VERSION 5.8 ;
BUSBITCHARS "[]" ;
DIVIDERCHAR "/" ;
UNITS
    DATABASE MICRONS 1000 ;
END UNITS

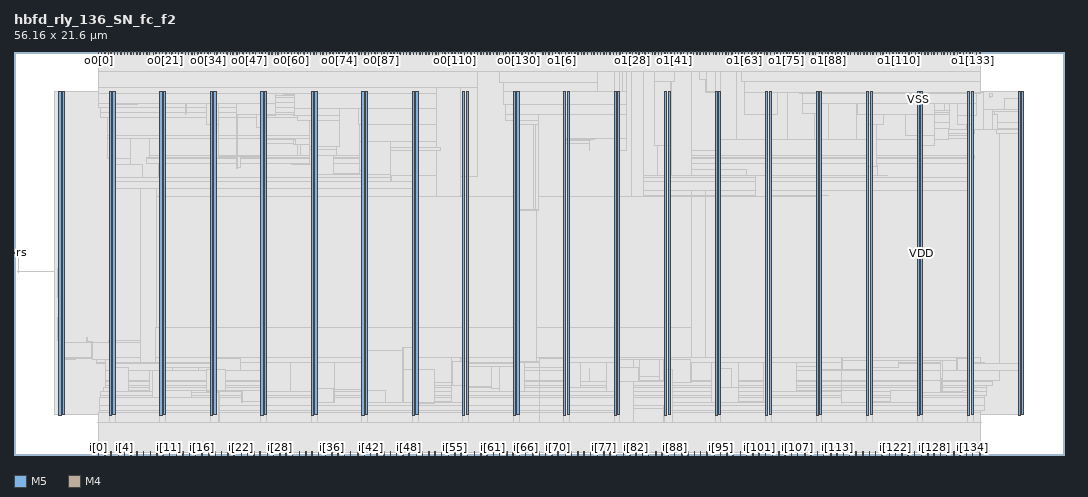
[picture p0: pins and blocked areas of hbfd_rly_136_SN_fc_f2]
MACRO hbfd_rly_136_SN_fc_f2
  FOREIGN hbfd_rly_136_SN_fc_f2 0 0 ;
  CLASS BLOCK ;
  SIZE 56.16 BY 21.6 ;
  PIN clk_in
    DIRECTION INPUT ;
    USE SIGNAL ;
    PORT
      LAYER M5 ;
        RECT  28.08 0 28.104 0.192 ;
    END
  END clk_in
  PIN clk_out0
    DIRECTION OUTPUT ;
    USE SIGNAL ;
    PORT
      LAYER M5 ;
        RECT  16.176 21.408 16.2 21.6 ;
    END
  END clk_out0
  PIN clk_out1
    DIRECTION OUTPUT ;
    USE SIGNAL ;
    PORT
      LAYER M5 ;
        RECT  39.936 21.408 39.96 21.6 ;
    END
  END clk_out1
  PIN i[0]
    DIRECTION INPUT ;
    USE SIGNAL ;
    PORT
      LAYER M5 ;
        RECT  4.512 0 4.536 0.192 ;
    END
  END i[0]
  PIN i[100]
    DIRECTION INPUT ;
    USE SIGNAL ;
    PORT
      LAYER M5 ;
        RECT  39.504 0 39.528 0.192 ;
    END
  END i[100]
  PIN i[101]
    DIRECTION INPUT ;
    USE SIGNAL ;
    PORT
      LAYER M5 ;
        RECT  39.84 0 39.864 0.192 ;
    END
  END i[101]
  PIN i[102]
    DIRECTION INPUT ;
    USE SIGNAL ;
    PORT
      LAYER M5 ;
        RECT  40.176 0 40.2 0.192 ;
    END
  END i[102]
  PIN i[103]
    DIRECTION INPUT ;
    USE SIGNAL ;
    PORT
      LAYER M5 ;
        RECT  40.56 0 40.584 0.192 ;
    END
  END i[103]
  PIN i[104]
    DIRECTION INPUT ;
    USE SIGNAL ;
    PORT
      LAYER M5 ;
        RECT  40.896 0 40.92 0.192 ;
    END
  END i[104]
  PIN i[105]
    DIRECTION INPUT ;
    USE SIGNAL ;
    PORT
      LAYER M5 ;
        RECT  41.232 0 41.256 0.192 ;
    END
  END i[105]
  PIN i[106]
    DIRECTION INPUT ;
    USE SIGNAL ;
    PORT
      LAYER M5 ;
        RECT  41.568 0 41.592 0.192 ;
    END
  END i[106]
  PIN i[107]
    DIRECTION INPUT ;
    USE SIGNAL ;
    PORT
      LAYER M5 ;
        RECT  41.904 0 41.928 0.192 ;
    END
  END i[107]
  PIN i[108]
    DIRECTION INPUT ;
    USE SIGNAL ;
    PORT
      LAYER M5 ;
        RECT  42.288 0 42.312 0.192 ;
    END
  END i[108]
  PIN i[109]
    DIRECTION INPUT ;
    USE SIGNAL ;
    PORT
      LAYER M5 ;
        RECT  42.624 0 42.648 0.192 ;
    END
  END i[109]
  PIN i[10]
    DIRECTION INPUT ;
    USE SIGNAL ;
    PORT
      LAYER M5 ;
        RECT  7.968 0 7.992 0.192 ;
    END
  END i[10]
  PIN i[110]
    DIRECTION INPUT ;
    USE SIGNAL ;
    PORT
      LAYER M5 ;
        RECT  42.96 0 42.984 0.192 ;
    END
  END i[110]
  PIN i[111]
    DIRECTION INPUT ;
    USE SIGNAL ;
    PORT
      LAYER M5 ;
        RECT  43.296 0 43.32 0.192 ;
    END
  END i[111]
  PIN i[112]
    DIRECTION INPUT ;
    USE SIGNAL ;
    PORT
      LAYER M5 ;
        RECT  43.68 0 43.704 0.192 ;
    END
  END i[112]
  PIN i[113]
    DIRECTION INPUT ;
    USE SIGNAL ;
    PORT
      LAYER M5 ;
        RECT  44.016 0 44.04 0.192 ;
    END
  END i[113]
  PIN i[114]
    DIRECTION INPUT ;
    USE SIGNAL ;
    PORT
      LAYER M5 ;
        RECT  44.352 0 44.376 0.192 ;
    END
  END i[114]
  PIN i[115]
    DIRECTION INPUT ;
    USE SIGNAL ;
    PORT
      LAYER M5 ;
        RECT  44.688 0 44.712 0.192 ;
    END
  END i[115]
  PIN i[116]
    DIRECTION INPUT ;
    USE SIGNAL ;
    PORT
      LAYER M5 ;
        RECT  45.024 0 45.048 0.192 ;
    END
  END i[116]
  PIN i[117]
    DIRECTION INPUT ;
    USE SIGNAL ;
    PORT
      LAYER M5 ;
        RECT  45.408 0 45.432 0.192 ;
    END
  END i[117]
  PIN i[118]
    DIRECTION INPUT ;
    USE SIGNAL ;
    PORT
      LAYER M5 ;
        RECT  45.744 0 45.768 0.192 ;
    END
  END i[118]
  PIN i[119]
    DIRECTION INPUT ;
    USE SIGNAL ;
    PORT
      LAYER M5 ;
        RECT  46.08 0 46.104 0.192 ;
    END
  END i[119]
  PIN i[11]
    DIRECTION INPUT ;
    USE SIGNAL ;
    PORT
      LAYER M5 ;
        RECT  8.304 0 8.328 0.192 ;
    END
  END i[11]
  PIN i[120]
    DIRECTION INPUT ;
    USE SIGNAL ;
    PORT
      LAYER M5 ;
        RECT  46.416 0 46.44 0.192 ;
    END
  END i[120]
  PIN i[121]
    DIRECTION INPUT ;
    USE SIGNAL ;
    PORT
      LAYER M5 ;
        RECT  46.8 0 46.824 0.192 ;
    END
  END i[121]
  PIN i[122]
    DIRECTION INPUT ;
    USE SIGNAL ;
    PORT
      LAYER M5 ;
        RECT  47.136 0 47.16 0.192 ;
    END
  END i[122]
  PIN i[123]
    DIRECTION INPUT ;
    USE SIGNAL ;
    PORT
      LAYER M5 ;
        RECT  47.472 0 47.496 0.192 ;
    END
  END i[123]
  PIN i[124]
    DIRECTION INPUT ;
    USE SIGNAL ;
    PORT
      LAYER M5 ;
        RECT  47.808 0 47.832 0.192 ;
    END
  END i[124]
  PIN i[125]
    DIRECTION INPUT ;
    USE SIGNAL ;
    PORT
      LAYER M5 ;
        RECT  48.144 0 48.168 0.192 ;
    END
  END i[125]
  PIN i[126]
    DIRECTION INPUT ;
    USE SIGNAL ;
    PORT
      LAYER M5 ;
        RECT  48.528 0 48.552 0.192 ;
    END
  END i[126]
  PIN i[127]
    DIRECTION INPUT ;
    USE SIGNAL ;
    PORT
      LAYER M5 ;
        RECT  48.864 0 48.888 0.192 ;
    END
  END i[127]
  PIN i[128]
    DIRECTION INPUT ;
    USE SIGNAL ;
    PORT
      LAYER M5 ;
        RECT  49.2 0 49.224 0.192 ;
    END
  END i[128]
  PIN i[129]
    DIRECTION INPUT ;
    USE SIGNAL ;
    PORT
      LAYER M5 ;
        RECT  49.536 0 49.56 0.192 ;
    END
  END i[129]
  PIN i[12]
    DIRECTION INPUT ;
    USE SIGNAL ;
    PORT
      LAYER M5 ;
        RECT  8.688 0 8.712 0.192 ;
    END
  END i[12]
  PIN i[130]
    DIRECTION INPUT ;
    USE SIGNAL ;
    PORT
      LAYER M5 ;
        RECT  49.872 0 49.896 0.192 ;
    END
  END i[130]
  PIN i[131]
    DIRECTION INPUT ;
    USE SIGNAL ;
    PORT
      LAYER M5 ;
        RECT  50.256 0 50.28 0.192 ;
    END
  END i[131]
  PIN i[132]
    DIRECTION INPUT ;
    USE SIGNAL ;
    PORT
      LAYER M5 ;
        RECT  50.592 0 50.616 0.192 ;
    END
  END i[132]
  PIN i[133]
    DIRECTION INPUT ;
    USE SIGNAL ;
    PORT
      LAYER M5 ;
        RECT  50.928 0 50.952 0.192 ;
    END
  END i[133]
  PIN i[134]
    DIRECTION INPUT ;
    USE SIGNAL ;
    PORT
      LAYER M5 ;
        RECT  51.264 0 51.288 0.192 ;
    END
  END i[134]
  PIN i[135]
    DIRECTION INPUT ;
    USE SIGNAL ;
    PORT
      LAYER M5 ;
        RECT  51.648 0 51.672 0.192 ;
    END
  END i[135]
  PIN i[13]
    DIRECTION INPUT ;
    USE SIGNAL ;
    PORT
      LAYER M5 ;
        RECT  9.024 0 9.048 0.192 ;
    END
  END i[13]
  PIN i[14]
    DIRECTION INPUT ;
    USE SIGNAL ;
    PORT
      LAYER M5 ;
        RECT  9.36 0 9.384 0.192 ;
    END
  END i[14]
  PIN i[15]
    DIRECTION INPUT ;
    USE SIGNAL ;
    PORT
      LAYER M5 ;
        RECT  9.696 0 9.72 0.192 ;
    END
  END i[15]
  PIN i[16]
    DIRECTION INPUT ;
    USE SIGNAL ;
    PORT
      LAYER M5 ;
        RECT  10.032 0 10.056 0.192 ;
    END
  END i[16]
  PIN i[17]
    DIRECTION INPUT ;
    USE SIGNAL ;
    PORT
      LAYER M5 ;
        RECT  10.416 0 10.44 0.192 ;
    END
  END i[17]
  PIN i[18]
    DIRECTION INPUT ;
    USE SIGNAL ;
    PORT
      LAYER M5 ;
        RECT  10.752 0 10.776 0.192 ;
    END
  END i[18]
  PIN i[19]
    DIRECTION INPUT ;
    USE SIGNAL ;
    PORT
      LAYER M5 ;
        RECT  11.088 0 11.112 0.192 ;
    END
  END i[19]
  PIN i[1]
    DIRECTION INPUT ;
    USE SIGNAL ;
    PORT
      LAYER M5 ;
        RECT  4.848 0 4.872 0.192 ;
    END
  END i[1]
  PIN i[20]
    DIRECTION INPUT ;
    USE SIGNAL ;
    PORT
      LAYER M5 ;
        RECT  11.424 0 11.448 0.192 ;
    END
  END i[20]
  PIN i[21]
    DIRECTION INPUT ;
    USE SIGNAL ;
    PORT
      LAYER M5 ;
        RECT  11.76 0 11.784 0.192 ;
    END
  END i[21]
  PIN i[22]
    DIRECTION INPUT ;
    USE SIGNAL ;
    PORT
      LAYER M5 ;
        RECT  12.144 0 12.168 0.192 ;
    END
  END i[22]
  PIN i[23]
    DIRECTION INPUT ;
    USE SIGNAL ;
    PORT
      LAYER M5 ;
        RECT  12.48 0 12.504 0.192 ;
    END
  END i[23]
  PIN i[24]
    DIRECTION INPUT ;
    USE SIGNAL ;
    PORT
      LAYER M5 ;
        RECT  12.816 0 12.84 0.192 ;
    END
  END i[24]
  PIN i[25]
    DIRECTION INPUT ;
    USE SIGNAL ;
    PORT
      LAYER M5 ;
        RECT  13.152 0 13.176 0.192 ;
    END
  END i[25]
  PIN i[26]
    DIRECTION INPUT ;
    USE SIGNAL ;
    PORT
      LAYER M5 ;
        RECT  13.536 0 13.56 0.192 ;
    END
  END i[26]
  PIN i[27]
    DIRECTION INPUT ;
    USE SIGNAL ;
    PORT
      LAYER M5 ;
        RECT  13.872 0 13.896 0.192 ;
    END
  END i[27]
  PIN i[28]
    DIRECTION INPUT ;
    USE SIGNAL ;
    PORT
      LAYER M5 ;
        RECT  14.208 0 14.232 0.192 ;
    END
  END i[28]
  PIN i[29]
    DIRECTION INPUT ;
    USE SIGNAL ;
    PORT
      LAYER M5 ;
        RECT  14.544 0 14.568 0.192 ;
    END
  END i[29]
  PIN i[2]
    DIRECTION INPUT ;
    USE SIGNAL ;
    PORT
      LAYER M5 ;
        RECT  5.184 0 5.208 0.192 ;
    END
  END i[2]
  PIN i[30]
    DIRECTION INPUT ;
    USE SIGNAL ;
    PORT
      LAYER M5 ;
        RECT  14.88 0 14.904 0.192 ;
    END
  END i[30]
  PIN i[31]
    DIRECTION INPUT ;
    USE SIGNAL ;
    PORT
      LAYER M5 ;
        RECT  15.264 0 15.288 0.192 ;
    END
  END i[31]
  PIN i[32]
    DIRECTION INPUT ;
    USE SIGNAL ;
    PORT
      LAYER M5 ;
        RECT  15.6 0 15.624 0.192 ;
    END
  END i[32]
  PIN i[33]
    DIRECTION INPUT ;
    USE SIGNAL ;
    PORT
      LAYER M5 ;
        RECT  15.936 0 15.96 0.192 ;
    END
  END i[33]
  PIN i[34]
    DIRECTION INPUT ;
    USE SIGNAL ;
    PORT
      LAYER M5 ;
        RECT  16.272 0 16.296 0.192 ;
    END
  END i[34]
  PIN i[35]
    DIRECTION INPUT ;
    USE SIGNAL ;
    PORT
      LAYER M5 ;
        RECT  16.656 0 16.68 0.192 ;
    END
  END i[35]
  PIN i[36]
    DIRECTION INPUT ;
    USE SIGNAL ;
    PORT
      LAYER M5 ;
        RECT  16.992 0 17.016 0.192 ;
    END
  END i[36]
  PIN i[37]
    DIRECTION INPUT ;
    USE SIGNAL ;
    PORT
      LAYER M5 ;
        RECT  17.328 0 17.352 0.192 ;
    END
  END i[37]
  PIN i[38]
    DIRECTION INPUT ;
    USE SIGNAL ;
    PORT
      LAYER M5 ;
        RECT  17.664 0 17.688 0.192 ;
    END
  END i[38]
  PIN i[39]
    DIRECTION INPUT ;
    USE SIGNAL ;
    PORT
      LAYER M5 ;
        RECT  18 0 18.024 0.192 ;
    END
  END i[39]
  PIN i[3]
    DIRECTION INPUT ;
    USE SIGNAL ;
    PORT
      LAYER M5 ;
        RECT  5.568 0 5.592 0.192 ;
    END
  END i[3]
  PIN i[40]
    DIRECTION INPUT ;
    USE SIGNAL ;
    PORT
      LAYER M5 ;
        RECT  18.384 0 18.408 0.192 ;
    END
  END i[40]
  PIN i[41]
    DIRECTION INPUT ;
    USE SIGNAL ;
    PORT
      LAYER M5 ;
        RECT  18.72 0 18.744 0.192 ;
    END
  END i[41]
  PIN i[42]
    DIRECTION INPUT ;
    USE SIGNAL ;
    PORT
      LAYER M5 ;
        RECT  19.056 0 19.08 0.192 ;
    END
  END i[42]
  PIN i[43]
    DIRECTION INPUT ;
    USE SIGNAL ;
    PORT
      LAYER M5 ;
        RECT  19.392 0 19.416 0.192 ;
    END
  END i[43]
  PIN i[44]
    DIRECTION INPUT ;
    USE SIGNAL ;
    PORT
      LAYER M5 ;
        RECT  19.776 0 19.8 0.192 ;
    END
  END i[44]
  PIN i[45]
    DIRECTION INPUT ;
    USE SIGNAL ;
    PORT
      LAYER M5 ;
        RECT  20.112 0 20.136 0.192 ;
    END
  END i[45]
  PIN i[46]
    DIRECTION INPUT ;
    USE SIGNAL ;
    PORT
      LAYER M5 ;
        RECT  20.448 0 20.472 0.192 ;
    END
  END i[46]
  PIN i[47]
    DIRECTION INPUT ;
    USE SIGNAL ;
    PORT
      LAYER M5 ;
        RECT  20.784 0 20.808 0.192 ;
    END
  END i[47]
  PIN i[48]
    DIRECTION INPUT ;
    USE SIGNAL ;
    PORT
      LAYER M5 ;
        RECT  21.12 0 21.144 0.192 ;
    END
  END i[48]
  PIN i[49]
    DIRECTION INPUT ;
    USE SIGNAL ;
    PORT
      LAYER M5 ;
        RECT  21.504 0 21.528 0.192 ;
    END
  END i[49]
  PIN i[4]
    DIRECTION INPUT ;
    USE SIGNAL ;
    PORT
      LAYER M5 ;
        RECT  5.904 0 5.928 0.192 ;
    END
  END i[4]
  PIN i[50]
    DIRECTION INPUT ;
    USE SIGNAL ;
    PORT
      LAYER M5 ;
        RECT  21.84 0 21.864 0.192 ;
    END
  END i[50]
  PIN i[51]
    DIRECTION INPUT ;
    USE SIGNAL ;
    PORT
      LAYER M5 ;
        RECT  22.176 0 22.2 0.192 ;
    END
  END i[51]
  PIN i[52]
    DIRECTION INPUT ;
    USE SIGNAL ;
    PORT
      LAYER M5 ;
        RECT  22.512 0 22.536 0.192 ;
    END
  END i[52]
  PIN i[53]
    DIRECTION INPUT ;
    USE SIGNAL ;
    PORT
      LAYER M5 ;
        RECT  22.848 0 22.872 0.192 ;
    END
  END i[53]
  PIN i[54]
    DIRECTION INPUT ;
    USE SIGNAL ;
    PORT
      LAYER M5 ;
        RECT  23.232 0 23.256 0.192 ;
    END
  END i[54]
  PIN i[55]
    DIRECTION INPUT ;
    USE SIGNAL ;
    PORT
      LAYER M5 ;
        RECT  23.568 0 23.592 0.192 ;
    END
  END i[55]
  PIN i[56]
    DIRECTION INPUT ;
    USE SIGNAL ;
    PORT
      LAYER M5 ;
        RECT  23.904 0 23.928 0.192 ;
    END
  END i[56]
  PIN i[57]
    DIRECTION INPUT ;
    USE SIGNAL ;
    PORT
      LAYER M5 ;
        RECT  24.24 0 24.264 0.192 ;
    END
  END i[57]
  PIN i[58]
    DIRECTION INPUT ;
    USE SIGNAL ;
    PORT
      LAYER M5 ;
        RECT  24.624 0 24.648 0.192 ;
    END
  END i[58]
  PIN i[59]
    DIRECTION INPUT ;
    USE SIGNAL ;
    PORT
      LAYER M5 ;
        RECT  24.96 0 24.984 0.192 ;
    END
  END i[59]
  PIN i[5]
    DIRECTION INPUT ;
    USE SIGNAL ;
    PORT
      LAYER M5 ;
        RECT  6.24 0 6.264 0.192 ;
    END
  END i[5]
  PIN i[60]
    DIRECTION INPUT ;
    USE SIGNAL ;
    PORT
      LAYER M5 ;
        RECT  25.296 0 25.32 0.192 ;
    END
  END i[60]
  PIN i[61]
    DIRECTION INPUT ;
    USE SIGNAL ;
    PORT
      LAYER M5 ;
        RECT  25.632 0 25.656 0.192 ;
    END
  END i[61]
  PIN i[62]
    DIRECTION INPUT ;
    USE SIGNAL ;
    PORT
      LAYER M5 ;
        RECT  25.968 0 25.992 0.192 ;
    END
  END i[62]
  PIN i[63]
    DIRECTION INPUT ;
    USE SIGNAL ;
    PORT
      LAYER M5 ;
        RECT  26.352 0 26.376 0.192 ;
    END
  END i[63]
  PIN i[64]
    DIRECTION INPUT ;
    USE SIGNAL ;
    PORT
      LAYER M5 ;
        RECT  26.688 0 26.712 0.192 ;
    END
  END i[64]
  PIN i[65]
    DIRECTION INPUT ;
    USE SIGNAL ;
    PORT
      LAYER M5 ;
        RECT  27.024 0 27.048 0.192 ;
    END
  END i[65]
  PIN i[66]
    DIRECTION INPUT ;
    USE SIGNAL ;
    PORT
      LAYER M5 ;
        RECT  27.36 0 27.384 0.192 ;
    END
  END i[66]
  PIN i[67]
    DIRECTION INPUT ;
    USE SIGNAL ;
    PORT
      LAYER M5 ;
        RECT  27.744 0 27.768 0.192 ;
    END
  END i[67]
  PIN i[68]
    DIRECTION INPUT ;
    USE SIGNAL ;
    PORT
      LAYER M5 ;
        RECT  28.416 0 28.44 0.192 ;
    END
  END i[68]
  PIN i[69]
    DIRECTION INPUT ;
    USE SIGNAL ;
    PORT
      LAYER M5 ;
        RECT  28.752 0 28.776 0.192 ;
    END
  END i[69]
  PIN i[6]
    DIRECTION INPUT ;
    USE SIGNAL ;
    PORT
      LAYER M5 ;
        RECT  6.576 0 6.6 0.192 ;
    END
  END i[6]
  PIN i[70]
    DIRECTION INPUT ;
    USE SIGNAL ;
    PORT
      LAYER M5 ;
        RECT  29.088 0 29.112 0.192 ;
    END
  END i[70]
  PIN i[71]
    DIRECTION INPUT ;
    USE SIGNAL ;
    PORT
      LAYER M5 ;
        RECT  29.472 0 29.496 0.192 ;
    END
  END i[71]
  PIN i[72]
    DIRECTION INPUT ;
    USE SIGNAL ;
    PORT
      LAYER M5 ;
        RECT  29.808 0 29.832 0.192 ;
    END
  END i[72]
  PIN i[73]
    DIRECTION INPUT ;
    USE SIGNAL ;
    PORT
      LAYER M5 ;
        RECT  30.144 0 30.168 0.192 ;
    END
  END i[73]
  PIN i[74]
    DIRECTION INPUT ;
    USE SIGNAL ;
    PORT
      LAYER M5 ;
        RECT  30.48 0 30.504 0.192 ;
    END
  END i[74]
  PIN i[75]
    DIRECTION INPUT ;
    USE SIGNAL ;
    PORT
      LAYER M5 ;
        RECT  30.816 0 30.84 0.192 ;
    END
  END i[75]
  PIN i[76]
    DIRECTION INPUT ;
    USE SIGNAL ;
    PORT
      LAYER M5 ;
        RECT  31.2 0 31.224 0.192 ;
    END
  END i[76]
  PIN i[77]
    DIRECTION INPUT ;
    USE SIGNAL ;
    PORT
      LAYER M5 ;
        RECT  31.536 0 31.56 0.192 ;
    END
  END i[77]
  PIN i[78]
    DIRECTION INPUT ;
    USE SIGNAL ;
    PORT
      LAYER M5 ;
        RECT  31.872 0 31.896 0.192 ;
    END
  END i[78]
  PIN i[79]
    DIRECTION INPUT ;
    USE SIGNAL ;
    PORT
      LAYER M5 ;
        RECT  32.208 0 32.232 0.192 ;
    END
  END i[79]
  PIN i[7]
    DIRECTION INPUT ;
    USE SIGNAL ;
    PORT
      LAYER M5 ;
        RECT  6.912 0 6.936 0.192 ;
    END
  END i[7]
  PIN i[80]
    DIRECTION INPUT ;
    USE SIGNAL ;
    PORT
      LAYER M5 ;
        RECT  32.592 0 32.616 0.192 ;
    END
  END i[80]
  PIN i[81]
    DIRECTION INPUT ;
    USE SIGNAL ;
    PORT
      LAYER M5 ;
        RECT  32.928 0 32.952 0.192 ;
    END
  END i[81]
  PIN i[82]
    DIRECTION INPUT ;
    USE SIGNAL ;
    PORT
      LAYER M5 ;
        RECT  33.264 0 33.288 0.192 ;
    END
  END i[82]
  PIN i[83]
    DIRECTION INPUT ;
    USE SIGNAL ;
    PORT
      LAYER M5 ;
        RECT  33.6 0 33.624 0.192 ;
    END
  END i[83]
  PIN i[84]
    DIRECTION INPUT ;
    USE SIGNAL ;
    PORT
      LAYER M5 ;
        RECT  33.936 0 33.96 0.192 ;
    END
  END i[84]
  PIN i[85]
    DIRECTION INPUT ;
    USE SIGNAL ;
    PORT
      LAYER M5 ;
        RECT  34.32 0 34.344 0.192 ;
    END
  END i[85]
  PIN i[86]
    DIRECTION INPUT ;
    USE SIGNAL ;
    PORT
      LAYER M5 ;
        RECT  34.656 0 34.68 0.192 ;
    END
  END i[86]
  PIN i[87]
    DIRECTION INPUT ;
    USE SIGNAL ;
    PORT
      LAYER M5 ;
        RECT  34.992 0 35.016 0.192 ;
    END
  END i[87]
  PIN i[88]
    DIRECTION INPUT ;
    USE SIGNAL ;
    PORT
      LAYER M5 ;
        RECT  35.328 0 35.352 0.192 ;
    END
  END i[88]
  PIN i[89]
    DIRECTION INPUT ;
    USE SIGNAL ;
    PORT
      LAYER M5 ;
        RECT  35.712 0 35.736 0.192 ;
    END
  END i[89]
  PIN i[8]
    DIRECTION INPUT ;
    USE SIGNAL ;
    PORT
      LAYER M5 ;
        RECT  7.296 0 7.32 0.192 ;
    END
  END i[8]
  PIN i[90]
    DIRECTION INPUT ;
    USE SIGNAL ;
    PORT
      LAYER M5 ;
        RECT  36.048 0 36.072 0.192 ;
    END
  END i[90]
  PIN i[91]
    DIRECTION INPUT ;
    USE SIGNAL ;
    PORT
      LAYER M5 ;
        RECT  36.384 0 36.408 0.192 ;
    END
  END i[91]
  PIN i[92]
    DIRECTION INPUT ;
    USE SIGNAL ;
    PORT
      LAYER M5 ;
        RECT  36.72 0 36.744 0.192 ;
    END
  END i[92]
  PIN i[93]
    DIRECTION INPUT ;
    USE SIGNAL ;
    PORT
      LAYER M5 ;
        RECT  37.056 0 37.08 0.192 ;
    END
  END i[93]
  PIN i[94]
    DIRECTION INPUT ;
    USE SIGNAL ;
    PORT
      LAYER M5 ;
        RECT  37.44 0 37.464 0.192 ;
    END
  END i[94]
  PIN i[95]
    DIRECTION INPUT ;
    USE SIGNAL ;
    PORT
      LAYER M5 ;
        RECT  37.776 0 37.8 0.192 ;
    END
  END i[95]
  PIN i[96]
    DIRECTION INPUT ;
    USE SIGNAL ;
    PORT
      LAYER M5 ;
        RECT  38.112 0 38.136 0.192 ;
    END
  END i[96]
  PIN i[97]
    DIRECTION INPUT ;
    USE SIGNAL ;
    PORT
      LAYER M5 ;
        RECT  38.448 0 38.472 0.192 ;
    END
  END i[97]
  PIN i[98]
    DIRECTION INPUT ;
    USE SIGNAL ;
    PORT
      LAYER M5 ;
        RECT  38.832 0 38.856 0.192 ;
    END
  END i[98]
  PIN i[99]
    DIRECTION INPUT ;
    USE SIGNAL ;
    PORT
      LAYER M5 ;
        RECT  39.168 0 39.192 0.192 ;
    END
  END i[99]
  PIN i[9]
    DIRECTION INPUT ;
    USE SIGNAL ;
    PORT
      LAYER M5 ;
        RECT  7.632 0 7.656 0.192 ;
    END
  END i[9]
  PIN o0[0]
    DIRECTION OUTPUT ;
    USE SIGNAL ;
    PORT
      LAYER M5 ;
        RECT  4.512 21.408 4.536 21.6 ;
    END
  END o0[0]
  PIN o0[100]
    DIRECTION OUTPUT ;
    USE SIGNAL ;
    PORT
      LAYER M5 ;
        RECT  21.84 21.408 21.864 21.6 ;
    END
  END o0[100]
  PIN o0[101]
    DIRECTION OUTPUT ;
    USE SIGNAL ;
    PORT
      LAYER M5 ;
        RECT  22.032 21.408 22.056 21.6 ;
    END
  END o0[101]
  PIN o0[102]
    DIRECTION OUTPUT ;
    USE SIGNAL ;
    PORT
      LAYER M5 ;
        RECT  22.176 21.408 22.2 21.6 ;
    END
  END o0[102]
  PIN o0[103]
    DIRECTION OUTPUT ;
    USE SIGNAL ;
    PORT
      LAYER M5 ;
        RECT  22.368 21.408 22.392 21.6 ;
    END
  END o0[103]
  PIN o0[104]
    DIRECTION OUTPUT ;
    USE SIGNAL ;
    PORT
      LAYER M5 ;
        RECT  22.56 21.408 22.584 21.6 ;
    END
  END o0[104]
  PIN o0[105]
    DIRECTION OUTPUT ;
    USE SIGNAL ;
    PORT
      LAYER M5 ;
        RECT  22.704 21.408 22.728 21.6 ;
    END
  END o0[105]
  PIN o0[106]
    DIRECTION OUTPUT ;
    USE SIGNAL ;
    PORT
      LAYER M5 ;
        RECT  22.896 21.408 22.92 21.6 ;
    END
  END o0[106]
  PIN o0[107]
    DIRECTION OUTPUT ;
    USE SIGNAL ;
    PORT
      LAYER M5 ;
        RECT  23.04 21.408 23.064 21.6 ;
    END
  END o0[107]
  PIN o0[108]
    DIRECTION OUTPUT ;
    USE SIGNAL ;
    PORT
      LAYER M5 ;
        RECT  23.232 21.408 23.256 21.6 ;
    END
  END o0[108]
  PIN o0[109]
    DIRECTION OUTPUT ;
    USE SIGNAL ;
    PORT
      LAYER M5 ;
        RECT  23.424 21.408 23.448 21.6 ;
    END
  END o0[109]
  PIN o0[10]
    DIRECTION OUTPUT ;
    USE SIGNAL ;
    PORT
      LAYER M5 ;
        RECT  6.24 21.408 6.264 21.6 ;
    END
  END o0[10]
  PIN o0[110]
    DIRECTION OUTPUT ;
    USE SIGNAL ;
    PORT
      LAYER M5 ;
        RECT  23.568 21.408 23.592 21.6 ;
    END
  END o0[110]
  PIN o0[111]
    DIRECTION OUTPUT ;
    USE SIGNAL ;
    PORT
      LAYER M5 ;
        RECT  23.76 21.408 23.784 21.6 ;
    END
  END o0[111]
  PIN o0[112]
    DIRECTION OUTPUT ;
    USE SIGNAL ;
    PORT
      LAYER M5 ;
        RECT  23.904 21.408 23.928 21.6 ;
    END
  END o0[112]
  PIN o0[113]
    DIRECTION OUTPUT ;
    USE SIGNAL ;
    PORT
      LAYER M5 ;
        RECT  24.096 21.408 24.12 21.6 ;
    END
  END o0[113]
  PIN o0[114]
    DIRECTION OUTPUT ;
    USE SIGNAL ;
    PORT
      LAYER M5 ;
        RECT  24.24 21.408 24.264 21.6 ;
    END
  END o0[114]
  PIN o0[115]
    DIRECTION OUTPUT ;
    USE SIGNAL ;
    PORT
      LAYER M5 ;
        RECT  24.432 21.408 24.456 21.6 ;
    END
  END o0[115]
  PIN o0[116]
    DIRECTION OUTPUT ;
    USE SIGNAL ;
    PORT
      LAYER M5 ;
        RECT  24.624 21.408 24.648 21.6 ;
    END
  END o0[116]
  PIN o0[117]
    DIRECTION OUTPUT ;
    USE SIGNAL ;
    PORT
      LAYER M5 ;
        RECT  24.768 21.408 24.792 21.6 ;
    END
  END o0[117]
  PIN o0[118]
    DIRECTION OUTPUT ;
    USE SIGNAL ;
    PORT
      LAYER M5 ;
        RECT  24.96 21.408 24.984 21.6 ;
    END
  END o0[118]
  PIN o0[119]
    DIRECTION OUTPUT ;
    USE SIGNAL ;
    PORT
      LAYER M5 ;
        RECT  25.104 21.408 25.128 21.6 ;
    END
  END o0[119]
  PIN o0[11]
    DIRECTION OUTPUT ;
    USE SIGNAL ;
    PORT
      LAYER M5 ;
        RECT  6.384 21.408 6.408 21.6 ;
    END
  END o0[11]
  PIN o0[120]
    DIRECTION OUTPUT ;
    USE SIGNAL ;
    PORT
      LAYER M5 ;
        RECT  25.296 21.408 25.32 21.6 ;
    END
  END o0[120]
  PIN o0[121]
    DIRECTION OUTPUT ;
    USE SIGNAL ;
    PORT
      LAYER M5 ;
        RECT  25.44 21.408 25.464 21.6 ;
    END
  END o0[121]
  PIN o0[122]
    DIRECTION OUTPUT ;
    USE SIGNAL ;
    PORT
      LAYER M5 ;
        RECT  25.632 21.408 25.656 21.6 ;
    END
  END o0[122]
  PIN o0[123]
    DIRECTION OUTPUT ;
    USE SIGNAL ;
    PORT
      LAYER M5 ;
        RECT  25.824 21.408 25.848 21.6 ;
    END
  END o0[123]
  PIN o0[124]
    DIRECTION OUTPUT ;
    USE SIGNAL ;
    PORT
      LAYER M5 ;
        RECT  25.968 21.408 25.992 21.6 ;
    END
  END o0[124]
  PIN o0[125]
    DIRECTION OUTPUT ;
    USE SIGNAL ;
    PORT
      LAYER M5 ;
        RECT  26.16 21.408 26.184 21.6 ;
    END
  END o0[125]
  PIN o0[126]
    DIRECTION OUTPUT ;
    USE SIGNAL ;
    PORT
      LAYER M5 ;
        RECT  26.304 21.408 26.328 21.6 ;
    END
  END o0[126]
  PIN o0[127]
    DIRECTION OUTPUT ;
    USE SIGNAL ;
    PORT
      LAYER M5 ;
        RECT  26.496 21.408 26.52 21.6 ;
    END
  END o0[127]
  PIN o0[128]
    DIRECTION OUTPUT ;
    USE SIGNAL ;
    PORT
      LAYER M5 ;
        RECT  26.688 21.408 26.712 21.6 ;
    END
  END o0[128]
  PIN o0[129]
    DIRECTION OUTPUT ;
    USE SIGNAL ;
    PORT
      LAYER M5 ;
        RECT  26.832 21.408 26.856 21.6 ;
    END
  END o0[129]
  PIN o0[12]
    DIRECTION OUTPUT ;
    USE SIGNAL ;
    PORT
      LAYER M5 ;
        RECT  6.576 21.408 6.6 21.6 ;
    END
  END o0[12]
  PIN o0[130]
    DIRECTION OUTPUT ;
    USE SIGNAL ;
    PORT
      LAYER M5 ;
        RECT  27.024 21.408 27.048 21.6 ;
    END
  END o0[130]
  PIN o0[131]
    DIRECTION OUTPUT ;
    USE SIGNAL ;
    PORT
      LAYER M5 ;
        RECT  27.168 21.408 27.192 21.6 ;
    END
  END o0[131]
  PIN o0[132]
    DIRECTION OUTPUT ;
    USE SIGNAL ;
    PORT
      LAYER M5 ;
        RECT  27.36 21.408 27.384 21.6 ;
    END
  END o0[132]
  PIN o0[133]
    DIRECTION OUTPUT ;
    USE SIGNAL ;
    PORT
      LAYER M5 ;
        RECT  27.504 21.408 27.528 21.6 ;
    END
  END o0[133]
  PIN o0[134]
    DIRECTION OUTPUT ;
    USE SIGNAL ;
    PORT
      LAYER M5 ;
        RECT  27.696 21.408 27.72 21.6 ;
    END
  END o0[134]
  PIN o0[135]
    DIRECTION OUTPUT ;
    USE SIGNAL ;
    PORT
      LAYER M5 ;
        RECT  27.888 21.408 27.912 21.6 ;
    END
  END o0[135]
  PIN o0[13]
    DIRECTION OUTPUT ;
    USE SIGNAL ;
    PORT
      LAYER M5 ;
        RECT  6.72 21.408 6.744 21.6 ;
    END
  END o0[13]
  PIN o0[14]
    DIRECTION OUTPUT ;
    USE SIGNAL ;
    PORT
      LAYER M5 ;
        RECT  6.912 21.408 6.936 21.6 ;
    END
  END o0[14]
  PIN o0[15]
    DIRECTION OUTPUT ;
    USE SIGNAL ;
    PORT
      LAYER M5 ;
        RECT  7.104 21.408 7.128 21.6 ;
    END
  END o0[15]
  PIN o0[16]
    DIRECTION OUTPUT ;
    USE SIGNAL ;
    PORT
      LAYER M5 ;
        RECT  7.248 21.408 7.272 21.6 ;
    END
  END o0[16]
  PIN o0[17]
    DIRECTION OUTPUT ;
    USE SIGNAL ;
    PORT
      LAYER M5 ;
        RECT  7.44 21.408 7.464 21.6 ;
    END
  END o0[17]
  PIN o0[18]
    DIRECTION OUTPUT ;
    USE SIGNAL ;
    PORT
      LAYER M5 ;
        RECT  7.584 21.408 7.608 21.6 ;
    END
  END o0[18]
  PIN o0[19]
    DIRECTION OUTPUT ;
    USE SIGNAL ;
    PORT
      LAYER M5 ;
        RECT  7.776 21.408 7.8 21.6 ;
    END
  END o0[19]
  PIN o0[1]
    DIRECTION OUTPUT ;
    USE SIGNAL ;
    PORT
      LAYER M5 ;
        RECT  4.656 21.408 4.68 21.6 ;
    END
  END o0[1]
  PIN o0[20]
    DIRECTION OUTPUT ;
    USE SIGNAL ;
    PORT
      LAYER M5 ;
        RECT  7.92 21.408 7.944 21.6 ;
    END
  END o0[20]
  PIN o0[21]
    DIRECTION OUTPUT ;
    USE SIGNAL ;
    PORT
      LAYER M5 ;
        RECT  8.112 21.408 8.136 21.6 ;
    END
  END o0[21]
  PIN o0[22]
    DIRECTION OUTPUT ;
    USE SIGNAL ;
    PORT
      LAYER M5 ;
        RECT  8.304 21.408 8.328 21.6 ;
    END
  END o0[22]
  PIN o0[23]
    DIRECTION OUTPUT ;
    USE SIGNAL ;
    PORT
      LAYER M5 ;
        RECT  8.448 21.408 8.472 21.6 ;
    END
  END o0[23]
  PIN o0[24]
    DIRECTION OUTPUT ;
    USE SIGNAL ;
    PORT
      LAYER M5 ;
        RECT  8.64 21.408 8.664 21.6 ;
    END
  END o0[24]
  PIN o0[25]
    DIRECTION OUTPUT ;
    USE SIGNAL ;
    PORT
      LAYER M5 ;
        RECT  8.784 21.408 8.808 21.6 ;
    END
  END o0[25]
  PIN o0[26]
    DIRECTION OUTPUT ;
    USE SIGNAL ;
    PORT
      LAYER M5 ;
        RECT  8.976 21.408 9 21.6 ;
    END
  END o0[26]
  PIN o0[27]
    DIRECTION OUTPUT ;
    USE SIGNAL ;
    PORT
      LAYER M5 ;
        RECT  9.168 21.408 9.192 21.6 ;
    END
  END o0[27]
  PIN o0[28]
    DIRECTION OUTPUT ;
    USE SIGNAL ;
    PORT
      LAYER M5 ;
        RECT  9.312 21.408 9.336 21.6 ;
    END
  END o0[28]
  PIN o0[29]
    DIRECTION OUTPUT ;
    USE SIGNAL ;
    PORT
      LAYER M5 ;
        RECT  9.504 21.408 9.528 21.6 ;
    END
  END o0[29]
  PIN o0[2]
    DIRECTION OUTPUT ;
    USE SIGNAL ;
    PORT
      LAYER M5 ;
        RECT  4.848 21.408 4.872 21.6 ;
    END
  END o0[2]
  PIN o0[30]
    DIRECTION OUTPUT ;
    USE SIGNAL ;
    PORT
      LAYER M5 ;
        RECT  9.648 21.408 9.672 21.6 ;
    END
  END o0[30]
  PIN o0[31]
    DIRECTION OUTPUT ;
    USE SIGNAL ;
    PORT
      LAYER M5 ;
        RECT  9.84 21.408 9.864 21.6 ;
    END
  END o0[31]
  PIN o0[32]
    DIRECTION OUTPUT ;
    USE SIGNAL ;
    PORT
      LAYER M5 ;
        RECT  9.984 21.408 10.008 21.6 ;
    END
  END o0[32]
  PIN o0[33]
    DIRECTION OUTPUT ;
    USE SIGNAL ;
    PORT
      LAYER M5 ;
        RECT  10.176 21.408 10.2 21.6 ;
    END
  END o0[33]
  PIN o0[34]
    DIRECTION OUTPUT ;
    USE SIGNAL ;
    PORT
      LAYER M5 ;
        RECT  10.368 21.408 10.392 21.6 ;
    END
  END o0[34]
  PIN o0[35]
    DIRECTION OUTPUT ;
    USE SIGNAL ;
    PORT
      LAYER M5 ;
        RECT  10.512 21.408 10.536 21.6 ;
    END
  END o0[35]
  PIN o0[36]
    DIRECTION OUTPUT ;
    USE SIGNAL ;
    PORT
      LAYER M5 ;
        RECT  10.704 21.408 10.728 21.6 ;
    END
  END o0[36]
  PIN o0[37]
    DIRECTION OUTPUT ;
    USE SIGNAL ;
    PORT
      LAYER M5 ;
        RECT  10.848 21.408 10.872 21.6 ;
    END
  END o0[37]
  PIN o0[38]
    DIRECTION OUTPUT ;
    USE SIGNAL ;
    PORT
      LAYER M5 ;
        RECT  11.04 21.408 11.064 21.6 ;
    END
  END o0[38]
  PIN o0[39]
    DIRECTION OUTPUT ;
    USE SIGNAL ;
    PORT
      LAYER M5 ;
        RECT  11.184 21.408 11.208 21.6 ;
    END
  END o0[39]
  PIN o0[3]
    DIRECTION OUTPUT ;
    USE SIGNAL ;
    PORT
      LAYER M5 ;
        RECT  5.04 21.408 5.064 21.6 ;
    END
  END o0[3]
  PIN o0[40]
    DIRECTION OUTPUT ;
    USE SIGNAL ;
    PORT
      LAYER M5 ;
        RECT  11.376 21.408 11.4 21.6 ;
    END
  END o0[40]
  PIN o0[41]
    DIRECTION OUTPUT ;
    USE SIGNAL ;
    PORT
      LAYER M5 ;
        RECT  11.568 21.408 11.592 21.6 ;
    END
  END o0[41]
  PIN o0[42]
    DIRECTION OUTPUT ;
    USE SIGNAL ;
    PORT
      LAYER M5 ;
        RECT  11.712 21.408 11.736 21.6 ;
    END
  END o0[42]
  PIN o0[43]
    DIRECTION OUTPUT ;
    USE SIGNAL ;
    PORT
      LAYER M5 ;
        RECT  11.904 21.408 11.928 21.6 ;
    END
  END o0[43]
  PIN o0[44]
    DIRECTION OUTPUT ;
    USE SIGNAL ;
    PORT
      LAYER M5 ;
        RECT  12.048 21.408 12.072 21.6 ;
    END
  END o0[44]
  PIN o0[45]
    DIRECTION OUTPUT ;
    USE SIGNAL ;
    PORT
      LAYER M5 ;
        RECT  12.24 21.408 12.264 21.6 ;
    END
  END o0[45]
  PIN o0[46]
    DIRECTION OUTPUT ;
    USE SIGNAL ;
    PORT
      LAYER M5 ;
        RECT  12.432 21.408 12.456 21.6 ;
    END
  END o0[46]
  PIN o0[47]
    DIRECTION OUTPUT ;
    USE SIGNAL ;
    PORT
      LAYER M5 ;
        RECT  12.576 21.408 12.6 21.6 ;
    END
  END o0[47]
  PIN o0[48]
    DIRECTION OUTPUT ;
    USE SIGNAL ;
    PORT
      LAYER M5 ;
        RECT  12.768 21.408 12.792 21.6 ;
    END
  END o0[48]
  PIN o0[49]
    DIRECTION OUTPUT ;
    USE SIGNAL ;
    PORT
      LAYER M5 ;
        RECT  12.912 21.408 12.936 21.6 ;
    END
  END o0[49]
  PIN o0[4]
    DIRECTION OUTPUT ;
    USE SIGNAL ;
    PORT
      LAYER M5 ;
        RECT  5.184 21.408 5.208 21.6 ;
    END
  END o0[4]
  PIN o0[50]
    DIRECTION OUTPUT ;
    USE SIGNAL ;
    PORT
      LAYER M5 ;
        RECT  13.104 21.408 13.128 21.6 ;
    END
  END o0[50]
  PIN o0[51]
    DIRECTION OUTPUT ;
    USE SIGNAL ;
    PORT
      LAYER M5 ;
        RECT  13.248 21.408 13.272 21.6 ;
    END
  END o0[51]
  PIN o0[52]
    DIRECTION OUTPUT ;
    USE SIGNAL ;
    PORT
      LAYER M5 ;
        RECT  13.44 21.408 13.464 21.6 ;
    END
  END o0[52]
  PIN o0[53]
    DIRECTION OUTPUT ;
    USE SIGNAL ;
    PORT
      LAYER M5 ;
        RECT  13.632 21.408 13.656 21.6 ;
    END
  END o0[53]
  PIN o0[54]
    DIRECTION OUTPUT ;
    USE SIGNAL ;
    PORT
      LAYER M5 ;
        RECT  13.776 21.408 13.8 21.6 ;
    END
  END o0[54]
  PIN o0[55]
    DIRECTION OUTPUT ;
    USE SIGNAL ;
    PORT
      LAYER M5 ;
        RECT  13.968 21.408 13.992 21.6 ;
    END
  END o0[55]
  PIN o0[56]
    DIRECTION OUTPUT ;
    USE SIGNAL ;
    PORT
      LAYER M5 ;
        RECT  14.112 21.408 14.136 21.6 ;
    END
  END o0[56]
  PIN o0[57]
    DIRECTION OUTPUT ;
    USE SIGNAL ;
    PORT
      LAYER M5 ;
        RECT  14.304 21.408 14.328 21.6 ;
    END
  END o0[57]
  PIN o0[58]
    DIRECTION OUTPUT ;
    USE SIGNAL ;
    PORT
      LAYER M5 ;
        RECT  14.448 21.408 14.472 21.6 ;
    END
  END o0[58]
  PIN o0[59]
    DIRECTION OUTPUT ;
    USE SIGNAL ;
    PORT
      LAYER M5 ;
        RECT  14.64 21.408 14.664 21.6 ;
    END
  END o0[59]
  PIN o0[5]
    DIRECTION OUTPUT ;
    USE SIGNAL ;
    PORT
      LAYER M5 ;
        RECT  5.376 21.408 5.4 21.6 ;
    END
  END o0[5]
  PIN o0[60]
    DIRECTION OUTPUT ;
    USE SIGNAL ;
    PORT
      LAYER M5 ;
        RECT  14.832 21.408 14.856 21.6 ;
    END
  END o0[60]
  PIN o0[61]
    DIRECTION OUTPUT ;
    USE SIGNAL ;
    PORT
      LAYER M5 ;
        RECT  14.976 21.408 15 21.6 ;
    END
  END o0[61]
  PIN o0[62]
    DIRECTION OUTPUT ;
    USE SIGNAL ;
    PORT
      LAYER M5 ;
        RECT  15.168 21.408 15.192 21.6 ;
    END
  END o0[62]
  PIN o0[63]
    DIRECTION OUTPUT ;
    USE SIGNAL ;
    PORT
      LAYER M5 ;
        RECT  15.312 21.408 15.336 21.6 ;
    END
  END o0[63]
  PIN o0[64]
    DIRECTION OUTPUT ;
    USE SIGNAL ;
    PORT
      LAYER M5 ;
        RECT  15.504 21.408 15.528 21.6 ;
    END
  END o0[64]
  PIN o0[65]
    DIRECTION OUTPUT ;
    USE SIGNAL ;
    PORT
      LAYER M5 ;
        RECT  15.696 21.408 15.72 21.6 ;
    END
  END o0[65]
  PIN o0[66]
    DIRECTION OUTPUT ;
    USE SIGNAL ;
    PORT
      LAYER M5 ;
        RECT  15.84 21.408 15.864 21.6 ;
    END
  END o0[66]
  PIN o0[67]
    DIRECTION OUTPUT ;
    USE SIGNAL ;
    PORT
      LAYER M5 ;
        RECT  16.032 21.408 16.056 21.6 ;
    END
  END o0[67]
  PIN o0[68]
    DIRECTION OUTPUT ;
    USE SIGNAL ;
    PORT
      LAYER M5 ;
        RECT  16.368 21.408 16.392 21.6 ;
    END
  END o0[68]
  PIN o0[69]
    DIRECTION OUTPUT ;
    USE SIGNAL ;
    PORT
      LAYER M5 ;
        RECT  16.512 21.408 16.536 21.6 ;
    END
  END o0[69]
  PIN o0[6]
    DIRECTION OUTPUT ;
    USE SIGNAL ;
    PORT
      LAYER M5 ;
        RECT  5.52 21.408 5.544 21.6 ;
    END
  END o0[6]
  PIN o0[70]
    DIRECTION OUTPUT ;
    USE SIGNAL ;
    PORT
      LAYER M5 ;
        RECT  16.704 21.408 16.728 21.6 ;
    END
  END o0[70]
  PIN o0[71]
    DIRECTION OUTPUT ;
    USE SIGNAL ;
    PORT
      LAYER M5 ;
        RECT  16.896 21.408 16.92 21.6 ;
    END
  END o0[71]
  PIN o0[72]
    DIRECTION OUTPUT ;
    USE SIGNAL ;
    PORT
      LAYER M5 ;
        RECT  17.04 21.408 17.064 21.6 ;
    END
  END o0[72]
  PIN o0[73]
    DIRECTION OUTPUT ;
    USE SIGNAL ;
    PORT
      LAYER M5 ;
        RECT  17.232 21.408 17.256 21.6 ;
    END
  END o0[73]
  PIN o0[74]
    DIRECTION OUTPUT ;
    USE SIGNAL ;
    PORT
      LAYER M5 ;
        RECT  17.376 21.408 17.4 21.6 ;
    END
  END o0[74]
  PIN o0[75]
    DIRECTION OUTPUT ;
    USE SIGNAL ;
    PORT
      LAYER M5 ;
        RECT  17.568 21.408 17.592 21.6 ;
    END
  END o0[75]
  PIN o0[76]
    DIRECTION OUTPUT ;
    USE SIGNAL ;
    PORT
      LAYER M5 ;
        RECT  17.712 21.408 17.736 21.6 ;
    END
  END o0[76]
  PIN o0[77]
    DIRECTION OUTPUT ;
    USE SIGNAL ;
    PORT
      LAYER M5 ;
        RECT  17.904 21.408 17.928 21.6 ;
    END
  END o0[77]
  PIN o0[78]
    DIRECTION OUTPUT ;
    USE SIGNAL ;
    PORT
      LAYER M5 ;
        RECT  18.096 21.408 18.12 21.6 ;
    END
  END o0[78]
  PIN o0[79]
    DIRECTION OUTPUT ;
    USE SIGNAL ;
    PORT
      LAYER M5 ;
        RECT  18.24 21.408 18.264 21.6 ;
    END
  END o0[79]
  PIN o0[7]
    DIRECTION OUTPUT ;
    USE SIGNAL ;
    PORT
      LAYER M5 ;
        RECT  5.712 21.408 5.736 21.6 ;
    END
  END o0[7]
  PIN o0[80]
    DIRECTION OUTPUT ;
    USE SIGNAL ;
    PORT
      LAYER M5 ;
        RECT  18.432 21.408 18.456 21.6 ;
    END
  END o0[80]
  PIN o0[81]
    DIRECTION OUTPUT ;
    USE SIGNAL ;
    PORT
      LAYER M5 ;
        RECT  18.576 21.408 18.6 21.6 ;
    END
  END o0[81]
  PIN o0[82]
    DIRECTION OUTPUT ;
    USE SIGNAL ;
    PORT
      LAYER M5 ;
        RECT  18.768 21.408 18.792 21.6 ;
    END
  END o0[82]
  PIN o0[83]
    DIRECTION OUTPUT ;
    USE SIGNAL ;
    PORT
      LAYER M5 ;
        RECT  18.96 21.408 18.984 21.6 ;
    END
  END o0[83]
  PIN o0[84]
    DIRECTION OUTPUT ;
    USE SIGNAL ;
    PORT
      LAYER M5 ;
        RECT  19.104 21.408 19.128 21.6 ;
    END
  END o0[84]
  PIN o0[85]
    DIRECTION OUTPUT ;
    USE SIGNAL ;
    PORT
      LAYER M5 ;
        RECT  19.296 21.408 19.32 21.6 ;
    END
  END o0[85]
  PIN o0[86]
    DIRECTION OUTPUT ;
    USE SIGNAL ;
    PORT
      LAYER M5 ;
        RECT  19.44 21.408 19.464 21.6 ;
    END
  END o0[86]
  PIN o0[87]
    DIRECTION OUTPUT ;
    USE SIGNAL ;
    PORT
      LAYER M5 ;
        RECT  19.632 21.408 19.656 21.6 ;
    END
  END o0[87]
  PIN o0[88]
    DIRECTION OUTPUT ;
    USE SIGNAL ;
    PORT
      LAYER M5 ;
        RECT  19.776 21.408 19.8 21.6 ;
    END
  END o0[88]
  PIN o0[89]
    DIRECTION OUTPUT ;
    USE SIGNAL ;
    PORT
      LAYER M5 ;
        RECT  19.968 21.408 19.992 21.6 ;
    END
  END o0[89]
  PIN o0[8]
    DIRECTION OUTPUT ;
    USE SIGNAL ;
    PORT
      LAYER M5 ;
        RECT  5.904 21.408 5.928 21.6 ;
    END
  END o0[8]
  PIN o0[90]
    DIRECTION OUTPUT ;
    USE SIGNAL ;
    PORT
      LAYER M5 ;
        RECT  20.16 21.408 20.184 21.6 ;
    END
  END o0[90]
  PIN o0[91]
    DIRECTION OUTPUT ;
    USE SIGNAL ;
    PORT
      LAYER M5 ;
        RECT  20.304 21.408 20.328 21.6 ;
    END
  END o0[91]
  PIN o0[92]
    DIRECTION OUTPUT ;
    USE SIGNAL ;
    PORT
      LAYER M5 ;
        RECT  20.496 21.408 20.52 21.6 ;
    END
  END o0[92]
  PIN o0[93]
    DIRECTION OUTPUT ;
    USE SIGNAL ;
    PORT
      LAYER M5 ;
        RECT  20.64 21.408 20.664 21.6 ;
    END
  END o0[93]
  PIN o0[94]
    DIRECTION OUTPUT ;
    USE SIGNAL ;
    PORT
      LAYER M5 ;
        RECT  20.832 21.408 20.856 21.6 ;
    END
  END o0[94]
  PIN o0[95]
    DIRECTION OUTPUT ;
    USE SIGNAL ;
    PORT
      LAYER M5 ;
        RECT  20.976 21.408 21 21.6 ;
    END
  END o0[95]
  PIN o0[96]
    DIRECTION OUTPUT ;
    USE SIGNAL ;
    PORT
      LAYER M5 ;
        RECT  21.168 21.408 21.192 21.6 ;
    END
  END o0[96]
  PIN o0[97]
    DIRECTION OUTPUT ;
    USE SIGNAL ;
    PORT
      LAYER M5 ;
        RECT  21.36 21.408 21.384 21.6 ;
    END
  END o0[97]
  PIN o0[98]
    DIRECTION OUTPUT ;
    USE SIGNAL ;
    PORT
      LAYER M5 ;
        RECT  21.504 21.408 21.528 21.6 ;
    END
  END o0[98]
  PIN o0[99]
    DIRECTION OUTPUT ;
    USE SIGNAL ;
    PORT
      LAYER M5 ;
        RECT  21.696 21.408 21.72 21.6 ;
    END
  END o0[99]
  PIN o0[9]
    DIRECTION OUTPUT ;
    USE SIGNAL ;
    PORT
      LAYER M5 ;
        RECT  6.048 21.408 6.072 21.6 ;
    END
  END o0[9]
  PIN o1[0]
    DIRECTION OUTPUT ;
    USE SIGNAL ;
    PORT
      LAYER M5 ;
        RECT  28.272 21.408 28.296 21.6 ;
    END
  END o1[0]
  PIN o1[100]
    DIRECTION OUTPUT ;
    USE SIGNAL ;
    PORT
      LAYER M5 ;
        RECT  45.6 21.408 45.624 21.6 ;
    END
  END o1[100]
  PIN o1[101]
    DIRECTION OUTPUT ;
    USE SIGNAL ;
    PORT
      LAYER M5 ;
        RECT  45.792 21.408 45.816 21.6 ;
    END
  END o1[101]
  PIN o1[102]
    DIRECTION OUTPUT ;
    USE SIGNAL ;
    PORT
      LAYER M5 ;
        RECT  45.936 21.408 45.96 21.6 ;
    END
  END o1[102]
  PIN o1[103]
    DIRECTION OUTPUT ;
    USE SIGNAL ;
    PORT
      LAYER M5 ;
        RECT  46.128 21.408 46.152 21.6 ;
    END
  END o1[103]
  PIN o1[104]
    DIRECTION OUTPUT ;
    USE SIGNAL ;
    PORT
      LAYER M5 ;
        RECT  46.32 21.408 46.344 21.6 ;
    END
  END o1[104]
  PIN o1[105]
    DIRECTION OUTPUT ;
    USE SIGNAL ;
    PORT
      LAYER M5 ;
        RECT  46.464 21.408 46.488 21.6 ;
    END
  END o1[105]
  PIN o1[106]
    DIRECTION OUTPUT ;
    USE SIGNAL ;
    PORT
      LAYER M5 ;
        RECT  46.656 21.408 46.68 21.6 ;
    END
  END o1[106]
  PIN o1[107]
    DIRECTION OUTPUT ;
    USE SIGNAL ;
    PORT
      LAYER M5 ;
        RECT  46.8 21.408 46.824 21.6 ;
    END
  END o1[107]
  PIN o1[108]
    DIRECTION OUTPUT ;
    USE SIGNAL ;
    PORT
      LAYER M5 ;
        RECT  46.992 21.408 47.016 21.6 ;
    END
  END o1[108]
  PIN o1[109]
    DIRECTION OUTPUT ;
    USE SIGNAL ;
    PORT
      LAYER M5 ;
        RECT  47.184 21.408 47.208 21.6 ;
    END
  END o1[109]
  PIN o1[10]
    DIRECTION OUTPUT ;
    USE SIGNAL ;
    PORT
      LAYER M5 ;
        RECT  30 21.408 30.024 21.6 ;
    END
  END o1[10]
  PIN o1[110]
    DIRECTION OUTPUT ;
    USE SIGNAL ;
    PORT
      LAYER M5 ;
        RECT  47.328 21.408 47.352 21.6 ;
    END
  END o1[110]
  PIN o1[111]
    DIRECTION OUTPUT ;
    USE SIGNAL ;
    PORT
      LAYER M5 ;
        RECT  47.52 21.408 47.544 21.6 ;
    END
  END o1[111]
  PIN o1[112]
    DIRECTION OUTPUT ;
    USE SIGNAL ;
    PORT
      LAYER M5 ;
        RECT  47.664 21.408 47.688 21.6 ;
    END
  END o1[112]
  PIN o1[113]
    DIRECTION OUTPUT ;
    USE SIGNAL ;
    PORT
      LAYER M5 ;
        RECT  47.856 21.408 47.88 21.6 ;
    END
  END o1[113]
  PIN o1[114]
    DIRECTION OUTPUT ;
    USE SIGNAL ;
    PORT
      LAYER M5 ;
        RECT  48 21.408 48.024 21.6 ;
    END
  END o1[114]
  PIN o1[115]
    DIRECTION OUTPUT ;
    USE SIGNAL ;
    PORT
      LAYER M5 ;
        RECT  48.192 21.408 48.216 21.6 ;
    END
  END o1[115]
  PIN o1[116]
    DIRECTION OUTPUT ;
    USE SIGNAL ;
    PORT
      LAYER M5 ;
        RECT  48.384 21.408 48.408 21.6 ;
    END
  END o1[116]
  PIN o1[117]
    DIRECTION OUTPUT ;
    USE SIGNAL ;
    PORT
      LAYER M5 ;
        RECT  48.528 21.408 48.552 21.6 ;
    END
  END o1[117]
  PIN o1[118]
    DIRECTION OUTPUT ;
    USE SIGNAL ;
    PORT
      LAYER M5 ;
        RECT  48.72 21.408 48.744 21.6 ;
    END
  END o1[118]
  PIN o1[119]
    DIRECTION OUTPUT ;
    USE SIGNAL ;
    PORT
      LAYER M5 ;
        RECT  48.864 21.408 48.888 21.6 ;
    END
  END o1[119]
  PIN o1[11]
    DIRECTION OUTPUT ;
    USE SIGNAL ;
    PORT
      LAYER M5 ;
        RECT  30.144 21.408 30.168 21.6 ;
    END
  END o1[11]
  PIN o1[120]
    DIRECTION OUTPUT ;
    USE SIGNAL ;
    PORT
      LAYER M5 ;
        RECT  49.056 21.408 49.08 21.6 ;
    END
  END o1[120]
  PIN o1[121]
    DIRECTION OUTPUT ;
    USE SIGNAL ;
    PORT
      LAYER M5 ;
        RECT  49.2 21.408 49.224 21.6 ;
    END
  END o1[121]
  PIN o1[122]
    DIRECTION OUTPUT ;
    USE SIGNAL ;
    PORT
      LAYER M5 ;
        RECT  49.392 21.408 49.416 21.6 ;
    END
  END o1[122]
  PIN o1[123]
    DIRECTION OUTPUT ;
    USE SIGNAL ;
    PORT
      LAYER M5 ;
        RECT  49.584 21.408 49.608 21.6 ;
    END
  END o1[123]
  PIN o1[124]
    DIRECTION OUTPUT ;
    USE SIGNAL ;
    PORT
      LAYER M5 ;
        RECT  49.728 21.408 49.752 21.6 ;
    END
  END o1[124]
  PIN o1[125]
    DIRECTION OUTPUT ;
    USE SIGNAL ;
    PORT
      LAYER M5 ;
        RECT  49.92 21.408 49.944 21.6 ;
    END
  END o1[125]
  PIN o1[126]
    DIRECTION OUTPUT ;
    USE SIGNAL ;
    PORT
      LAYER M5 ;
        RECT  50.064 21.408 50.088 21.6 ;
    END
  END o1[126]
  PIN o1[127]
    DIRECTION OUTPUT ;
    USE SIGNAL ;
    PORT
      LAYER M5 ;
        RECT  50.256 21.408 50.28 21.6 ;
    END
  END o1[127]
  PIN o1[128]
    DIRECTION OUTPUT ;
    USE SIGNAL ;
    PORT
      LAYER M5 ;
        RECT  50.448 21.408 50.472 21.6 ;
    END
  END o1[128]
  PIN o1[129]
    DIRECTION OUTPUT ;
    USE SIGNAL ;
    PORT
      LAYER M5 ;
        RECT  50.592 21.408 50.616 21.6 ;
    END
  END o1[129]
  PIN o1[12]
    DIRECTION OUTPUT ;
    USE SIGNAL ;
    PORT
      LAYER M5 ;
        RECT  30.336 21.408 30.36 21.6 ;
    END
  END o1[12]
  PIN o1[130]
    DIRECTION OUTPUT ;
    USE SIGNAL ;
    PORT
      LAYER M5 ;
        RECT  50.784 21.408 50.808 21.6 ;
    END
  END o1[130]
  PIN o1[131]
    DIRECTION OUTPUT ;
    USE SIGNAL ;
    PORT
      LAYER M5 ;
        RECT  50.928 21.408 50.952 21.6 ;
    END
  END o1[131]
  PIN o1[132]
    DIRECTION OUTPUT ;
    USE SIGNAL ;
    PORT
      LAYER M5 ;
        RECT  51.12 21.408 51.144 21.6 ;
    END
  END o1[132]
  PIN o1[133]
    DIRECTION OUTPUT ;
    USE SIGNAL ;
    PORT
      LAYER M5 ;
        RECT  51.264 21.408 51.288 21.6 ;
    END
  END o1[133]
  PIN o1[134]
    DIRECTION OUTPUT ;
    USE SIGNAL ;
    PORT
      LAYER M5 ;
        RECT  51.456 21.408 51.48 21.6 ;
    END
  END o1[134]
  PIN o1[135]
    DIRECTION OUTPUT ;
    USE SIGNAL ;
    PORT
      LAYER M5 ;
        RECT  51.648 21.408 51.672 21.6 ;
    END
  END o1[135]
  PIN o1[13]
    DIRECTION OUTPUT ;
    USE SIGNAL ;
    PORT
      LAYER M5 ;
        RECT  30.48 21.408 30.504 21.6 ;
    END
  END o1[13]
  PIN o1[14]
    DIRECTION OUTPUT ;
    USE SIGNAL ;
    PORT
      LAYER M5 ;
        RECT  30.672 21.408 30.696 21.6 ;
    END
  END o1[14]
  PIN o1[15]
    DIRECTION OUTPUT ;
    USE SIGNAL ;
    PORT
      LAYER M5 ;
        RECT  30.864 21.408 30.888 21.6 ;
    END
  END o1[15]
  PIN o1[16]
    DIRECTION OUTPUT ;
    USE SIGNAL ;
    PORT
      LAYER M5 ;
        RECT  31.008 21.408 31.032 21.6 ;
    END
  END o1[16]
  PIN o1[17]
    DIRECTION OUTPUT ;
    USE SIGNAL ;
    PORT
      LAYER M5 ;
        RECT  31.2 21.408 31.224 21.6 ;
    END
  END o1[17]
  PIN o1[18]
    DIRECTION OUTPUT ;
    USE SIGNAL ;
    PORT
      LAYER M5 ;
        RECT  31.344 21.408 31.368 21.6 ;
    END
  END o1[18]
  PIN o1[19]
    DIRECTION OUTPUT ;
    USE SIGNAL ;
    PORT
      LAYER M5 ;
        RECT  31.536 21.408 31.56 21.6 ;
    END
  END o1[19]
  PIN o1[1]
    DIRECTION OUTPUT ;
    USE SIGNAL ;
    PORT
      LAYER M5 ;
        RECT  28.416 21.408 28.44 21.6 ;
    END
  END o1[1]
  PIN o1[20]
    DIRECTION OUTPUT ;
    USE SIGNAL ;
    PORT
      LAYER M5 ;
        RECT  31.68 21.408 31.704 21.6 ;
    END
  END o1[20]
  PIN o1[21]
    DIRECTION OUTPUT ;
    USE SIGNAL ;
    PORT
      LAYER M5 ;
        RECT  31.872 21.408 31.896 21.6 ;
    END
  END o1[21]
  PIN o1[22]
    DIRECTION OUTPUT ;
    USE SIGNAL ;
    PORT
      LAYER M5 ;
        RECT  32.064 21.408 32.088 21.6 ;
    END
  END o1[22]
  PIN o1[23]
    DIRECTION OUTPUT ;
    USE SIGNAL ;
    PORT
      LAYER M5 ;
        RECT  32.208 21.408 32.232 21.6 ;
    END
  END o1[23]
  PIN o1[24]
    DIRECTION OUTPUT ;
    USE SIGNAL ;
    PORT
      LAYER M5 ;
        RECT  32.4 21.408 32.424 21.6 ;
    END
  END o1[24]
  PIN o1[25]
    DIRECTION OUTPUT ;
    USE SIGNAL ;
    PORT
      LAYER M5 ;
        RECT  32.544 21.408 32.568 21.6 ;
    END
  END o1[25]
  PIN o1[26]
    DIRECTION OUTPUT ;
    USE SIGNAL ;
    PORT
      LAYER M5 ;
        RECT  32.736 21.408 32.76 21.6 ;
    END
  END o1[26]
  PIN o1[27]
    DIRECTION OUTPUT ;
    USE SIGNAL ;
    PORT
      LAYER M5 ;
        RECT  32.928 21.408 32.952 21.6 ;
    END
  END o1[27]
  PIN o1[28]
    DIRECTION OUTPUT ;
    USE SIGNAL ;
    PORT
      LAYER M5 ;
        RECT  33.072 21.408 33.096 21.6 ;
    END
  END o1[28]
  PIN o1[29]
    DIRECTION OUTPUT ;
    USE SIGNAL ;
    PORT
      LAYER M5 ;
        RECT  33.264 21.408 33.288 21.6 ;
    END
  END o1[29]
  PIN o1[2]
    DIRECTION OUTPUT ;
    USE SIGNAL ;
    PORT
      LAYER M5 ;
        RECT  28.608 21.408 28.632 21.6 ;
    END
  END o1[2]
  PIN o1[30]
    DIRECTION OUTPUT ;
    USE SIGNAL ;
    PORT
      LAYER M5 ;
        RECT  33.408 21.408 33.432 21.6 ;
    END
  END o1[30]
  PIN o1[31]
    DIRECTION OUTPUT ;
    USE SIGNAL ;
    PORT
      LAYER M5 ;
        RECT  33.6 21.408 33.624 21.6 ;
    END
  END o1[31]
  PIN o1[32]
    DIRECTION OUTPUT ;
    USE SIGNAL ;
    PORT
      LAYER M5 ;
        RECT  33.744 21.408 33.768 21.6 ;
    END
  END o1[32]
  PIN o1[33]
    DIRECTION OUTPUT ;
    USE SIGNAL ;
    PORT
      LAYER M5 ;
        RECT  33.936 21.408 33.96 21.6 ;
    END
  END o1[33]
  PIN o1[34]
    DIRECTION OUTPUT ;
    USE SIGNAL ;
    PORT
      LAYER M5 ;
        RECT  34.128 21.408 34.152 21.6 ;
    END
  END o1[34]
  PIN o1[35]
    DIRECTION OUTPUT ;
    USE SIGNAL ;
    PORT
      LAYER M5 ;
        RECT  34.272 21.408 34.296 21.6 ;
    END
  END o1[35]
  PIN o1[36]
    DIRECTION OUTPUT ;
    USE SIGNAL ;
    PORT
      LAYER M5 ;
        RECT  34.464 21.408 34.488 21.6 ;
    END
  END o1[36]
  PIN o1[37]
    DIRECTION OUTPUT ;
    USE SIGNAL ;
    PORT
      LAYER M5 ;
        RECT  34.608 21.408 34.632 21.6 ;
    END
  END o1[37]
  PIN o1[38]
    DIRECTION OUTPUT ;
    USE SIGNAL ;
    PORT
      LAYER M5 ;
        RECT  34.8 21.408 34.824 21.6 ;
    END
  END o1[38]
  PIN o1[39]
    DIRECTION OUTPUT ;
    USE SIGNAL ;
    PORT
      LAYER M5 ;
        RECT  34.944 21.408 34.968 21.6 ;
    END
  END o1[39]
  PIN o1[3]
    DIRECTION OUTPUT ;
    USE SIGNAL ;
    PORT
      LAYER M5 ;
        RECT  28.8 21.408 28.824 21.6 ;
    END
  END o1[3]
  PIN o1[40]
    DIRECTION OUTPUT ;
    USE SIGNAL ;
    PORT
      LAYER M5 ;
        RECT  35.136 21.408 35.16 21.6 ;
    END
  END o1[40]
  PIN o1[41]
    DIRECTION OUTPUT ;
    USE SIGNAL ;
    PORT
      LAYER M5 ;
        RECT  35.328 21.408 35.352 21.6 ;
    END
  END o1[41]
  PIN o1[42]
    DIRECTION OUTPUT ;
    USE SIGNAL ;
    PORT
      LAYER M5 ;
        RECT  35.472 21.408 35.496 21.6 ;
    END
  END o1[42]
  PIN o1[43]
    DIRECTION OUTPUT ;
    USE SIGNAL ;
    PORT
      LAYER M5 ;
        RECT  35.664 21.408 35.688 21.6 ;
    END
  END o1[43]
  PIN o1[44]
    DIRECTION OUTPUT ;
    USE SIGNAL ;
    PORT
      LAYER M5 ;
        RECT  35.808 21.408 35.832 21.6 ;
    END
  END o1[44]
  PIN o1[45]
    DIRECTION OUTPUT ;
    USE SIGNAL ;
    PORT
      LAYER M5 ;
        RECT  36 21.408 36.024 21.6 ;
    END
  END o1[45]
  PIN o1[46]
    DIRECTION OUTPUT ;
    USE SIGNAL ;
    PORT
      LAYER M5 ;
        RECT  36.192 21.408 36.216 21.6 ;
    END
  END o1[46]
  PIN o1[47]
    DIRECTION OUTPUT ;
    USE SIGNAL ;
    PORT
      LAYER M5 ;
        RECT  36.336 21.408 36.36 21.6 ;
    END
  END o1[47]
  PIN o1[48]
    DIRECTION OUTPUT ;
    USE SIGNAL ;
    PORT
      LAYER M5 ;
        RECT  36.528 21.408 36.552 21.6 ;
    END
  END o1[48]
  PIN o1[49]
    DIRECTION OUTPUT ;
    USE SIGNAL ;
    PORT
      LAYER M5 ;
        RECT  36.672 21.408 36.696 21.6 ;
    END
  END o1[49]
  PIN o1[4]
    DIRECTION OUTPUT ;
    USE SIGNAL ;
    PORT
      LAYER M5 ;
        RECT  28.944 21.408 28.968 21.6 ;
    END
  END o1[4]
  PIN o1[50]
    DIRECTION OUTPUT ;
    USE SIGNAL ;
    PORT
      LAYER M5 ;
        RECT  36.864 21.408 36.888 21.6 ;
    END
  END o1[50]
  PIN o1[51]
    DIRECTION OUTPUT ;
    USE SIGNAL ;
    PORT
      LAYER M5 ;
        RECT  37.008 21.408 37.032 21.6 ;
    END
  END o1[51]
  PIN o1[52]
    DIRECTION OUTPUT ;
    USE SIGNAL ;
    PORT
      LAYER M5 ;
        RECT  37.2 21.408 37.224 21.6 ;
    END
  END o1[52]
  PIN o1[53]
    DIRECTION OUTPUT ;
    USE SIGNAL ;
    PORT
      LAYER M5 ;
        RECT  37.392 21.408 37.416 21.6 ;
    END
  END o1[53]
  PIN o1[54]
    DIRECTION OUTPUT ;
    USE SIGNAL ;
    PORT
      LAYER M5 ;
        RECT  37.536 21.408 37.56 21.6 ;
    END
  END o1[54]
  PIN o1[55]
    DIRECTION OUTPUT ;
    USE SIGNAL ;
    PORT
      LAYER M5 ;
        RECT  37.728 21.408 37.752 21.6 ;
    END
  END o1[55]
  PIN o1[56]
    DIRECTION OUTPUT ;
    USE SIGNAL ;
    PORT
      LAYER M5 ;
        RECT  37.872 21.408 37.896 21.6 ;
    END
  END o1[56]
  PIN o1[57]
    DIRECTION OUTPUT ;
    USE SIGNAL ;
    PORT
      LAYER M5 ;
        RECT  38.064 21.408 38.088 21.6 ;
    END
  END o1[57]
  PIN o1[58]
    DIRECTION OUTPUT ;
    USE SIGNAL ;
    PORT
      LAYER M5 ;
        RECT  38.208 21.408 38.232 21.6 ;
    END
  END o1[58]
  PIN o1[59]
    DIRECTION OUTPUT ;
    USE SIGNAL ;
    PORT
      LAYER M5 ;
        RECT  38.4 21.408 38.424 21.6 ;
    END
  END o1[59]
  PIN o1[5]
    DIRECTION OUTPUT ;
    USE SIGNAL ;
    PORT
      LAYER M5 ;
        RECT  29.136 21.408 29.16 21.6 ;
    END
  END o1[5]
  PIN o1[60]
    DIRECTION OUTPUT ;
    USE SIGNAL ;
    PORT
      LAYER M5 ;
        RECT  38.592 21.408 38.616 21.6 ;
    END
  END o1[60]
  PIN o1[61]
    DIRECTION OUTPUT ;
    USE SIGNAL ;
    PORT
      LAYER M5 ;
        RECT  38.736 21.408 38.76 21.6 ;
    END
  END o1[61]
  PIN o1[62]
    DIRECTION OUTPUT ;
    USE SIGNAL ;
    PORT
      LAYER M5 ;
        RECT  38.928 21.408 38.952 21.6 ;
    END
  END o1[62]
  PIN o1[63]
    DIRECTION OUTPUT ;
    USE SIGNAL ;
    PORT
      LAYER M5 ;
        RECT  39.072 21.408 39.096 21.6 ;
    END
  END o1[63]
  PIN o1[64]
    DIRECTION OUTPUT ;
    USE SIGNAL ;
    PORT
      LAYER M5 ;
        RECT  39.264 21.408 39.288 21.6 ;
    END
  END o1[64]
  PIN o1[65]
    DIRECTION OUTPUT ;
    USE SIGNAL ;
    PORT
      LAYER M5 ;
        RECT  39.456 21.408 39.48 21.6 ;
    END
  END o1[65]
  PIN o1[66]
    DIRECTION OUTPUT ;
    USE SIGNAL ;
    PORT
      LAYER M5 ;
        RECT  39.6 21.408 39.624 21.6 ;
    END
  END o1[66]
  PIN o1[67]
    DIRECTION OUTPUT ;
    USE SIGNAL ;
    PORT
      LAYER M5 ;
        RECT  39.792 21.408 39.816 21.6 ;
    END
  END o1[67]
  PIN o1[68]
    DIRECTION OUTPUT ;
    USE SIGNAL ;
    PORT
      LAYER M5 ;
        RECT  40.128 21.408 40.152 21.6 ;
    END
  END o1[68]
  PIN o1[69]
    DIRECTION OUTPUT ;
    USE SIGNAL ;
    PORT
      LAYER M5 ;
        RECT  40.272 21.408 40.296 21.6 ;
    END
  END o1[69]
  PIN o1[6]
    DIRECTION OUTPUT ;
    USE SIGNAL ;
    PORT
      LAYER M5 ;
        RECT  29.28 21.408 29.304 21.6 ;
    END
  END o1[6]
  PIN o1[70]
    DIRECTION OUTPUT ;
    USE SIGNAL ;
    PORT
      LAYER M5 ;
        RECT  40.464 21.408 40.488 21.6 ;
    END
  END o1[70]
  PIN o1[71]
    DIRECTION OUTPUT ;
    USE SIGNAL ;
    PORT
      LAYER M5 ;
        RECT  40.656 21.408 40.68 21.6 ;
    END
  END o1[71]
  PIN o1[72]
    DIRECTION OUTPUT ;
    USE SIGNAL ;
    PORT
      LAYER M5 ;
        RECT  40.8 21.408 40.824 21.6 ;
    END
  END o1[72]
  PIN o1[73]
    DIRECTION OUTPUT ;
    USE SIGNAL ;
    PORT
      LAYER M5 ;
        RECT  40.992 21.408 41.016 21.6 ;
    END
  END o1[73]
  PIN o1[74]
    DIRECTION OUTPUT ;
    USE SIGNAL ;
    PORT
      LAYER M5 ;
        RECT  41.136 21.408 41.16 21.6 ;
    END
  END o1[74]
  PIN o1[75]
    DIRECTION OUTPUT ;
    USE SIGNAL ;
    PORT
      LAYER M5 ;
        RECT  41.328 21.408 41.352 21.6 ;
    END
  END o1[75]
  PIN o1[76]
    DIRECTION OUTPUT ;
    USE SIGNAL ;
    PORT
      LAYER M5 ;
        RECT  41.472 21.408 41.496 21.6 ;
    END
  END o1[76]
  PIN o1[77]
    DIRECTION OUTPUT ;
    USE SIGNAL ;
    PORT
      LAYER M5 ;
        RECT  41.664 21.408 41.688 21.6 ;
    END
  END o1[77]
  PIN o1[78]
    DIRECTION OUTPUT ;
    USE SIGNAL ;
    PORT
      LAYER M5 ;
        RECT  41.856 21.408 41.88 21.6 ;
    END
  END o1[78]
  PIN o1[79]
    DIRECTION OUTPUT ;
    USE SIGNAL ;
    PORT
      LAYER M5 ;
        RECT  42 21.408 42.024 21.6 ;
    END
  END o1[79]
  PIN o1[7]
    DIRECTION OUTPUT ;
    USE SIGNAL ;
    PORT
      LAYER M5 ;
        RECT  29.472 21.408 29.496 21.6 ;
    END
  END o1[7]
  PIN o1[80]
    DIRECTION OUTPUT ;
    USE SIGNAL ;
    PORT
      LAYER M5 ;
        RECT  42.192 21.408 42.216 21.6 ;
    END
  END o1[80]
  PIN o1[81]
    DIRECTION OUTPUT ;
    USE SIGNAL ;
    PORT
      LAYER M5 ;
        RECT  42.336 21.408 42.36 21.6 ;
    END
  END o1[81]
  PIN o1[82]
    DIRECTION OUTPUT ;
    USE SIGNAL ;
    PORT
      LAYER M5 ;
        RECT  42.528 21.408 42.552 21.6 ;
    END
  END o1[82]
  PIN o1[83]
    DIRECTION OUTPUT ;
    USE SIGNAL ;
    PORT
      LAYER M5 ;
        RECT  42.72 21.408 42.744 21.6 ;
    END
  END o1[83]
  PIN o1[84]
    DIRECTION OUTPUT ;
    USE SIGNAL ;
    PORT
      LAYER M5 ;
        RECT  42.864 21.408 42.888 21.6 ;
    END
  END o1[84]
  PIN o1[85]
    DIRECTION OUTPUT ;
    USE SIGNAL ;
    PORT
      LAYER M5 ;
        RECT  43.056 21.408 43.08 21.6 ;
    END
  END o1[85]
  PIN o1[86]
    DIRECTION OUTPUT ;
    USE SIGNAL ;
    PORT
      LAYER M5 ;
        RECT  43.2 21.408 43.224 21.6 ;
    END
  END o1[86]
  PIN o1[87]
    DIRECTION OUTPUT ;
    USE SIGNAL ;
    PORT
      LAYER M5 ;
        RECT  43.392 21.408 43.416 21.6 ;
    END
  END o1[87]
  PIN o1[88]
    DIRECTION OUTPUT ;
    USE SIGNAL ;
    PORT
      LAYER M5 ;
        RECT  43.536 21.408 43.56 21.6 ;
    END
  END o1[88]
  PIN o1[89]
    DIRECTION OUTPUT ;
    USE SIGNAL ;
    PORT
      LAYER M5 ;
        RECT  43.728 21.408 43.752 21.6 ;
    END
  END o1[89]
  PIN o1[8]
    DIRECTION OUTPUT ;
    USE SIGNAL ;
    PORT
      LAYER M5 ;
        RECT  29.664 21.408 29.688 21.6 ;
    END
  END o1[8]
  PIN o1[90]
    DIRECTION OUTPUT ;
    USE SIGNAL ;
    PORT
      LAYER M5 ;
        RECT  43.92 21.408 43.944 21.6 ;
    END
  END o1[90]
  PIN o1[91]
    DIRECTION OUTPUT ;
    USE SIGNAL ;
    PORT
      LAYER M5 ;
        RECT  44.064 21.408 44.088 21.6 ;
    END
  END o1[91]
  PIN o1[92]
    DIRECTION OUTPUT ;
    USE SIGNAL ;
    PORT
      LAYER M5 ;
        RECT  44.256 21.408 44.28 21.6 ;
    END
  END o1[92]
  PIN o1[93]
    DIRECTION OUTPUT ;
    USE SIGNAL ;
    PORT
      LAYER M5 ;
        RECT  44.4 21.408 44.424 21.6 ;
    END
  END o1[93]
  PIN o1[94]
    DIRECTION OUTPUT ;
    USE SIGNAL ;
    PORT
      LAYER M5 ;
        RECT  44.592 21.408 44.616 21.6 ;
    END
  END o1[94]
  PIN o1[95]
    DIRECTION OUTPUT ;
    USE SIGNAL ;
    PORT
      LAYER M5 ;
        RECT  44.736 21.408 44.76 21.6 ;
    END
  END o1[95]
  PIN o1[96]
    DIRECTION OUTPUT ;
    USE SIGNAL ;
    PORT
      LAYER M5 ;
        RECT  44.928 21.408 44.952 21.6 ;
    END
  END o1[96]
  PIN o1[97]
    DIRECTION OUTPUT ;
    USE SIGNAL ;
    PORT
      LAYER M5 ;
        RECT  45.12 21.408 45.144 21.6 ;
    END
  END o1[97]
  PIN o1[98]
    DIRECTION OUTPUT ;
    USE SIGNAL ;
    PORT
      LAYER M5 ;
        RECT  45.264 21.408 45.288 21.6 ;
    END
  END o1[98]
  PIN o1[99]
    DIRECTION OUTPUT ;
    USE SIGNAL ;
    PORT
      LAYER M5 ;
        RECT  45.456 21.408 45.48 21.6 ;
    END
  END o1[99]
  PIN o1[9]
    DIRECTION OUTPUT ;
    USE SIGNAL ;
    PORT
      LAYER M5 ;
        RECT  29.808 21.408 29.832 21.6 ;
    END
  END o1[9]
  PIN rs
    DIRECTION INPUT ;
    USE SIGNAL ;
    PORT
      LAYER M4 ;
        RECT  0 10.8 0.192 10.824 ;
    END
  END rs
  PIN VDD
    DIRECTION INOUT ;
    USE POWER ;
    PORT
      LAYER M5 ;
        RECT  53.892 2.151 54.012 19.449 ;
        RECT  51.192 2.151 51.312 19.449 ;
        RECT  48.492 2.151 48.612 19.449 ;
        RECT  45.792 2.151 45.912 19.449 ;
        RECT  43.092 2.151 43.212 19.449 ;
        RECT  40.392 2.151 40.512 19.449 ;
        RECT  37.692 2.151 37.812 19.449 ;
        RECT  34.992 2.151 35.112 19.449 ;
        RECT  32.292 2.151 32.412 19.449 ;
        RECT  29.592 2.151 29.712 19.449 ;
        RECT  26.892 2.151 27.012 19.449 ;
        RECT  24.192 2.151 24.312 19.449 ;
        RECT  21.492 2.151 21.612 19.449 ;
        RECT  18.792 2.151 18.912 19.449 ;
        RECT  16.092 2.151 16.212 19.449 ;
        RECT  13.392 2.151 13.512 19.449 ;
        RECT  10.692 2.151 10.812 19.449 ;
        RECT  7.992 2.151 8.112 19.449 ;
        RECT  5.292 2.151 5.412 19.449 ;
        RECT  2.592 2.151 2.712 19.449 ;
    END
  END VDD
  PIN VSS
    DIRECTION INOUT ;
    USE GROUND ;
    PORT
      LAYER M5 ;
        RECT  53.7 2.137 53.82 19.463 ;
        RECT  51 2.137 51.12 19.463 ;
        RECT  48.3 2.137 48.42 19.463 ;
        RECT  45.6 2.137 45.72 19.463 ;
        RECT  42.9 2.137 43.02 19.463 ;
        RECT  40.2 2.137 40.32 19.463 ;
        RECT  37.5 2.137 37.62 19.463 ;
        RECT  34.8 2.137 34.92 19.463 ;
        RECT  32.1 2.137 32.22 19.463 ;
        RECT  29.4 2.137 29.52 19.463 ;
        RECT  26.7 2.137 26.82 19.463 ;
        RECT  24 2.137 24.12 19.463 ;
        RECT  21.3 2.137 21.42 19.463 ;
        RECT  18.6 2.137 18.72 19.463 ;
        RECT  15.9 2.137 16.02 19.463 ;
        RECT  13.2 2.137 13.32 19.463 ;
        RECT  10.5 2.137 10.62 19.463 ;
        RECT  7.8 2.137 7.92 19.463 ;
        RECT  5.1 2.137 5.22 19.463 ;
        RECT  2.4 2.137 2.52 19.463 ;
    END
  END VSS
  OBS
    LAYER RVTN ;
     RECT  2.16 2.16 54 2.295 ;
     RECT  2.16 2.565 54 2.835 ;
     RECT  2.16 3.105 54 3.375 ;
     RECT  2.16 3.645 54 3.915 ;
     RECT  2.16 4.185 54 4.455 ;
     RECT  2.16 4.725 54 4.995 ;
     RECT  2.16 5.265 54 5.535 ;
     RECT  2.16 5.805 54 6.075 ;
     RECT  2.16 6.345 54 6.615 ;
     RECT  2.16 6.885 54 7.155 ;
     RECT  2.16 7.425 54 7.695 ;
     RECT  2.16 7.965 54 8.235 ;
     RECT  2.16 8.505 54 8.775 ;
     RECT  2.16 9.045 54 9.315 ;
     RECT  2.16 9.585 54 9.855 ;
     RECT  2.16 10.125 54 10.395 ;
     RECT  2.16 10.665 54 10.935 ;
     RECT  2.16 11.205 54 11.475 ;
     RECT  2.16 11.745 54 12.015 ;
     RECT  2.16 12.285 54 12.555 ;
     RECT  2.16 12.825 54 13.095 ;
     RECT  2.16 13.365 54 13.635 ;
     RECT  2.16 13.905 54 14.175 ;
     RECT  2.16 14.445 54 14.715 ;
     RECT  2.16 14.985 54 15.255 ;
     RECT  2.16 15.525 54 15.795 ;
     RECT  2.16 16.065 54 16.335 ;
     RECT  2.16 16.605 54 16.875 ;
     RECT  2.16 17.145 54 17.415 ;
     RECT  2.16 17.685 54 17.955 ;
     RECT  2.16 18.225 54 18.495 ;
     RECT  2.16 18.765 54 19.035 ;
     RECT  2.16 19.305 54 19.44 ;
    LAYER RVTP ;
     RECT  2.16 2.295 54 2.565 ;
     RECT  2.16 2.835 54 3.105 ;
     RECT  2.16 3.375 54 3.645 ;
     RECT  2.16 3.915 54 4.185 ;
     RECT  2.16 4.455 54 4.725 ;
     RECT  2.16 4.995 54 5.265 ;
     RECT  2.16 5.535 54 5.805 ;
     RECT  2.16 6.075 54 6.345 ;
     RECT  2.16 6.615 54 6.885 ;
     RECT  2.16 7.155 54 7.425 ;
     RECT  2.16 7.695 54 7.965 ;
     RECT  2.16 8.235 54 8.505 ;
     RECT  2.16 8.775 54 9.045 ;
     RECT  2.16 9.315 54 9.585 ;
     RECT  2.16 9.855 54 10.125 ;
     RECT  2.16 10.395 54 10.665 ;
     RECT  2.16 10.935 54 11.205 ;
     RECT  2.16 11.475 54 11.745 ;
     RECT  2.16 12.015 54 12.285 ;
     RECT  2.16 12.555 54 12.825 ;
     RECT  2.16 13.095 54 13.365 ;
     RECT  2.16 13.635 54 13.905 ;
     RECT  2.16 14.175 54 14.445 ;
     RECT  2.16 14.715 54 14.985 ;
     RECT  2.16 15.255 54 15.525 ;
     RECT  2.16 15.795 54 16.065 ;
     RECT  2.16 16.335 54 16.605 ;
     RECT  2.16 16.875 54 17.145 ;
     RECT  2.16 17.415 54 17.685 ;
     RECT  2.16 17.955 54 18.225 ;
     RECT  2.16 18.495 54 18.765 ;
     RECT  2.16 19.035 54 19.305 ;
    LAYER M1 ;
     RECT  2.16 2.151 54 19.449 ;
    LAYER M2 ;
     RECT  0.211 9.792 2.16 9.81 ;
     RECT  2.16 2.151 15.331 19.449 ;
     RECT  15.331 2.151 17.123 19.989 ;
     RECT  17.123 2.151 22.783 19.719 ;
     RECT  22.783 2.151 23.323 20.259 ;
     RECT  23.323 2.151 24.475 20.304 ;
     RECT  27.751 21.366 28.031 21.384 ;
     RECT  24.475 2.151 31.199 20.448 ;
     RECT  31.199 2.151 33.647 20.412 ;
     RECT  33.647 2.151 38.399 20.376 ;
     RECT  38.399 2.151 44.627 20.34 ;
     RECT  44.627 2.151 46.787 19.674 ;
     RECT  46.787 2.151 54 19.449 ;
     RECT  54 2.421 54.012 19.179 ;
    LAYER M3 ;
     RECT  4.536 1.723 51.714 2.255 ;
     RECT  4.572 2.255 51.714 2.371 ;
     RECT  2.415 2.143 2.505 2.413 ;
     RECT  53.715 2.143 53.805 2.413 ;
     RECT  4.572 2.371 51.894 2.641 ;
     RECT  4.572 2.641 51.93 3.065 ;
     RECT  4.608 3.065 51.93 3.181 ;
     RECT  4.608 3.181 52.038 3.371 ;
     RECT  4.788 3.371 52.038 3.605 ;
     RECT  4.896 3.605 52.038 3.721 ;
     RECT  4.896 3.721 52.326 3.955 ;
     RECT  4.896 3.955 52.362 3.991 ;
     RECT  4.896 3.991 52.722 4.531 ;
     RECT  53.715 2.413 53.997 4.531 ;
     RECT  4.896 4.531 53.997 4.891 ;
     RECT  4.428 4.891 53.997 4.919 ;
     RECT  4.428 4.919 51.93 4.955 ;
     RECT  2.415 2.413 2.697 5.131 ;
     RECT  7.56 4.955 51.714 5.189 ;
     RECT  4.428 4.955 6.786 5.197 ;
     RECT  7.56 5.189 51.297 5.225 ;
     RECT  2.415 5.131 3.294 5.233 ;
     RECT  4.032 5.197 6.786 5.233 ;
     RECT  2.415 5.233 6.786 5.999 ;
     RECT  3.888 5.999 4.194 6.071 ;
     RECT  2.415 5.999 2.697 6.115 ;
     RECT  5.04 5.999 6.786 6.143 ;
     RECT  3.888 6.071 3.906 6.269 ;
     RECT  7.56 5.225 36.234 6.845 ;
     RECT  2.304 6.115 2.697 7.349 ;
     RECT  2.376 7.349 2.697 8.437 ;
     RECT  2.304 8.437 2.697 9.959 ;
     RECT  0.216 9.787 0.234 10.829 ;
     RECT  7.596 6.845 36.234 13.829 ;
     RECT  28.152 13.829 36.234 14.143 ;
     RECT  37.008 5.225 51.297 14.143 ;
     RECT  5.115 6.143 6.786 14.251 ;
     RECT  7.596 13.829 27.27 14.251 ;
     RECT  5.115 14.251 27.27 14.611 ;
     RECT  28.152 14.143 51.297 14.611 ;
     RECT  5.115 14.611 51.297 14.819 ;
     RECT  5.115 14.819 6.894 15.521 ;
     RECT  7.74 14.819 51.297 15.601 ;
     RECT  5.115 15.521 6.246 15.835 ;
     RECT  7.092 15.601 51.297 15.871 ;
     RECT  7.092 15.871 51.39 15.899 ;
     RECT  7.272 15.899 51.39 16.025 ;
     RECT  5.004 15.835 6.246 16.951 ;
     RECT  7.272 16.025 15.138 16.951 ;
     RECT  15.915 16.025 51.297 16.951 ;
     RECT  5.004 16.951 51.297 17.069 ;
     RECT  18.252 17.069 51.297 17.221 ;
     RECT  52.704 4.919 53.997 17.221 ;
     RECT  18.252 17.221 51.39 17.761 ;
     RECT  52.56 17.221 53.997 17.761 ;
     RECT  5.004 17.069 16.197 18.031 ;
     RECT  16.992 17.069 17.442 18.121 ;
     RECT  18.252 17.761 51.426 18.221 ;
     RECT  16.992 18.121 17.514 18.229 ;
     RECT  18.252 18.221 51.39 18.229 ;
     RECT  4.644 18.031 16.197 18.301 ;
     RECT  16.992 18.229 51.39 18.301 ;
     RECT  52.452 17.761 53.997 18.391 ;
     RECT  52.308 18.391 53.997 18.461 ;
     RECT  4.644 18.301 51.39 18.571 ;
     RECT  4.536 18.571 51.39 18.845 ;
     RECT  52.992 18.461 53.997 19.067 ;
     RECT  5.004 18.845 51.39 19.139 ;
     RECT  2.415 9.959 2.697 19.187 ;
     RECT  53.715 19.067 53.997 19.187 ;
     RECT  52.2 19.111 52.218 19.201 ;
     RECT  5.004 19.139 17.73 19.229 ;
     RECT  18.615 19.139 51.39 19.229 ;
     RECT  5.004 19.229 17.658 19.265 ;
     RECT  50.472 19.229 51.39 19.265 ;
     RECT  5.004 19.265 9.162 19.301 ;
     RECT  9.972 19.265 16.254 19.337 ;
     RECT  18.615 19.229 49.734 19.337 ;
     RECT  52.2 19.201 52.326 19.337 ;
     RECT  50.508 19.265 51.39 19.339 ;
     RECT  5.004 19.301 9.054 19.373 ;
     RECT  14.832 19.337 16.182 19.373 ;
     RECT  19.836 19.337 49.734 19.373 ;
     RECT  11.808 19.337 13.95 19.379 ;
     RECT  50.508 19.339 51.858 19.379 ;
     RECT  5.004 19.373 6.426 19.421 ;
     RECT  7.272 19.373 9.054 19.421 ;
     RECT  21.132 19.373 49.734 19.421 ;
     RECT  2.415 19.187 2.505 19.457 ;
     RECT  18.615 19.337 18.705 19.457 ;
     RECT  21.132 19.421 49.662 19.457 ;
     RECT  53.715 19.187 53.805 19.457 ;
     RECT  10.188 19.337 10.89 19.565 ;
     RECT  15.336 19.373 16.182 19.565 ;
     RECT  21.132 19.457 21.186 19.565 ;
     RECT  21.924 19.457 49.662 19.565 ;
     RECT  50.508 19.379 51.174 19.565 ;
     RECT  5.004 19.421 6.138 19.613 ;
     RECT  7.488 19.421 7.974 19.613 ;
     RECT  15.336 19.565 15.822 19.613 ;
     RECT  50.508 19.565 50.994 19.613 ;
     RECT  12.924 19.379 13.95 19.709 ;
     RECT  21.924 19.565 45.522 19.805 ;
     RECT  15.336 19.613 15.354 19.994 ;
     RECT  5.04 19.613 6.138 19.997 ;
     RECT  7.488 19.613 7.722 19.997 ;
     RECT  9.036 19.421 9.054 19.997 ;
     RECT  32.904 19.805 45.522 19.997 ;
     RECT  46.26 19.565 49.662 19.997 ;
     RECT  50.508 19.613 50.958 19.997 ;
     RECT  47.556 19.997 48.078 20.045 ;
     RECT  21.924 19.805 32.058 20.093 ;
     RECT  43.596 19.997 45.522 20.093 ;
     RECT  47.556 20.045 47.574 20.093 ;
     RECT  50.508 19.997 50.922 20.093 ;
     RECT  21.924 20.093 29.106 20.141 ;
     RECT  28.872 20.141 29.106 20.189 ;
     RECT  20.016 19.373 20.034 20.285 ;
     RECT  32.904 19.997 42.858 20.309 ;
     RECT  5.04 19.997 5.058 20.573 ;
     RECT  5.796 19.997 5.814 20.573 ;
     RECT  7.488 19.997 7.506 20.573 ;
     RECT  10.188 19.565 10.206 20.573 ;
     RECT  11.808 19.379 11.826 20.573 ;
     RECT  12.924 19.709 12.942 20.573 ;
     RECT  13.932 19.709 13.95 20.573 ;
     RECT  17.1 19.265 17.658 20.573 ;
     RECT  21.924 20.141 28.062 20.573 ;
     RECT  29.844 20.093 32.058 20.573 ;
     RECT  32.904 20.309 41.346 20.573 ;
     RECT  42.156 20.309 42.858 20.573 ;
     RECT  43.704 20.093 45.522 20.573 ;
     RECT  46.584 19.997 46.674 20.573 ;
     RECT  48.996 19.997 49.014 20.573 ;
     RECT  50.508 20.093 50.526 20.573 ;
     RECT  27.288 20.573 27.342 20.621 ;
     RECT  28.872 20.189 28.89 20.621 ;
     RECT  31.32 20.573 32.058 20.621 ;
     RECT  33.012 20.573 33.714 20.621 ;
     RECT  36.036 20.573 36.45 20.621 ;
     RECT  37.476 20.573 38.754 20.621 ;
     RECT  39.996 20.573 40.374 20.621 ;
     RECT  42.84 20.573 42.858 20.621 ;
     RECT  46.656 20.573 46.674 20.621 ;
     RECT  24.408 20.573 26.01 20.669 ;
     RECT  30.204 20.573 30.222 20.669 ;
     RECT  33.012 20.621 33.21 20.669 ;
     RECT  36.036 20.621 36.198 20.669 ;
     RECT  38.196 20.621 38.754 20.669 ;
     RECT  39.996 20.621 40.014 20.669 ;
     RECT  24.408 20.669 25.614 20.717 ;
     RECT  31.32 20.621 32.022 20.717 ;
     RECT  27.324 20.621 27.342 21.149 ;
     RECT  17.1 20.573 17.118 21.197 ;
     RECT  31.32 20.717 31.77 21.197 ;
     RECT  24.408 20.717 25.074 21.245 ;
     RECT  31.752 21.197 31.77 21.245 ;
     RECT  24.408 21.245 24.426 21.293 ;
     RECT  36.036 20.669 36.054 21.293 ;
     RECT  18.792 21.163 18.81 21.341 ;
     RECT  34.56 20.573 34.578 21.341 ;
     RECT  27.756 21.352 27.774 21.355 ;
     RECT  21.924 20.573 22.23 21.389 ;
     RECT  27.756 21.355 28.026 21.389 ;
     RECT  27.864 21.389 28.026 21.395 ;
     RECT  21.132 19.565 21.15 21.437 ;
     RECT  33.012 20.669 33.03 21.485 ;
     RECT  27.864 21.395 27.882 21.533 ;
    LAYER M4 ;
     RECT  0.156 10.8 0.245 10.824 ;
     RECT  2.408 2.148 2.512 19.452 ;
     RECT  2.512 2.418 2.704 19.182 ;
     RECT  2.704 5.136 4.124 5.16 ;
     RECT  4.124 5.136 4.885 6.024 ;
     RECT  4.501 18.816 4.988 18.84 ;
     RECT  4.645 20.544 4.988 20.568 ;
     RECT  4.481 1.728 5.108 1.752 ;
     RECT  4.885 4.512 5.108 6.024 ;
     RECT  4.988 18.816 5.108 20.568 ;
     RECT  5.108 1.728 5.404 20.568 ;
     RECT  5.404 18.768 5.825 20.568 ;
     RECT  5.404 4.512 6.131 4.68 ;
     RECT  5.825 18.768 6.275 19.992 ;
     RECT  6.275 18.768 6.617 19.416 ;
     RECT  5.404 3.408 7.225 3.432 ;
     RECT  6.131 4.512 7.225 4.536 ;
     RECT  7.225 3.408 7.405 4.536 ;
     RECT  7.429 20.544 7.517 20.568 ;
     RECT  6.617 18.816 7.573 19.416 ;
     RECT  7.573 18.816 7.693 19.56 ;
     RECT  5.404 1.728 7.808 1.752 ;
     RECT  7.405 3.072 7.808 4.536 ;
     RECT  7.693 18.816 7.808 19.992 ;
     RECT  7.808 1.728 7.811 19.992 ;
     RECT  7.811 1.728 7.996 19.608 ;
     RECT  7.996 1.728 8.104 19.56 ;
     RECT  8.104 4.512 8.489 4.68 ;
     RECT  8.104 18.816 8.965 19.56 ;
     RECT  8.965 18.816 9.065 19.992 ;
     RECT  9.065 18.816 9.137 19.272 ;
     RECT  9.137 18.816 9.157 18.936 ;
     RECT  9.157 18.24 9.245 18.936 ;
     RECT  8.104 3.072 9.497 3.432 ;
     RECT  8.489 4.656 9.853 4.68 ;
     RECT  9.245 18.816 10.165 18.936 ;
     RECT  9.829 20.544 10.217 20.568 ;
     RECT  10.165 18.816 10.309 19.368 ;
     RECT  10.309 17.712 10.357 17.736 ;
     RECT  10.309 18.816 10.357 19.608 ;
     RECT  8.104 1.728 10.508 1.752 ;
     RECT  9.497 3.36 10.508 3.432 ;
     RECT  9.853 4.512 10.508 4.68 ;
     RECT  10.357 17.712 10.508 19.608 ;
     RECT  10.508 1.728 10.547 19.608 ;
     RECT  10.547 1.728 10.804 19.56 ;
     RECT  10.804 18.816 10.924 19.56 ;
     RECT  10.924 18.816 10.945 19.464 ;
     RECT  10.804 1.728 10.973 3.432 ;
     RECT  11.701 20.544 11.837 20.568 ;
     RECT  10.804 15.936 11.893 15.96 ;
     RECT  10.804 4.512 12.089 5.16 ;
     RECT  11.893 15.36 12.125 15.96 ;
     RECT  10.973 3.408 12.157 3.432 ;
     RECT  10.945 18.816 12.229 19.368 ;
     RECT  12.157 2.832 12.241 3.432 ;
     RECT  12.229 18.24 12.565 19.368 ;
     RECT  12.565 18.24 12.949 19.416 ;
     RECT  10.973 1.728 13.208 1.752 ;
     RECT  12.241 2.88 13.208 3.432 ;
     RECT  12.089 4.512 13.208 4.968 ;
     RECT  12.125 15.936 13.208 15.96 ;
     RECT  12.949 17.52 13.208 19.416 ;
     RECT  13.208 1.728 13.237 19.452 ;
     RECT  12.901 20.544 13.237 20.568 ;
     RECT  13.237 1.728 13.504 20.568 ;
     RECT  13.504 18.192 13.781 20.568 ;
     RECT  13.781 19.248 13.961 20.568 ;
     RECT  13.961 19.248 14.393 20.088 ;
     RECT  13.504 16.656 14.929 16.872 ;
     RECT  13.781 18.192 14.965 18.216 ;
     RECT  14.929 16.608 15.073 16.872 ;
     RECT  14.965 18.144 15.157 18.216 ;
     RECT  14.393 19.296 15.685 20.088 ;
     RECT  14.629 21.264 15.685 21.288 ;
     RECT  15.157 17.904 15.757 18.216 ;
     RECT  15.685 19.296 15.757 21.288 ;
     RECT  14.821 15.552 15.781 15.576 ;
     RECT  15.073 16.608 15.781 16.92 ;
     RECT  13.504 1.728 15.908 1.752 ;
     RECT  13.504 3.408 15.908 4.968 ;
     RECT  15.781 15.552 15.908 16.92 ;
     RECT  15.757 17.904 15.908 21.288 ;
     RECT  15.908 1.728 16.021 21.288 ;
     RECT  16.021 1.728 16.204 21.384 ;
     RECT  16.204 2.832 17.123 4.968 ;
     RECT  16.204 16.08 17.221 21.384 ;
     RECT  16.204 15.024 18.469 15.048 ;
     RECT  17.221 16.032 18.469 21.384 ;
     RECT  16.204 1.728 18.608 1.752 ;
     RECT  17.123 3.504 18.608 4.968 ;
     RECT  18.469 15.024 18.608 21.384 ;
     RECT  18.608 1.728 18.661 21.384 ;
     RECT  18.661 1.728 18.904 21.48 ;
     RECT  18.904 15.024 20.149 21.48 ;
     RECT  18.904 2.832 20.789 5.592 ;
     RECT  18.904 1.728 21.308 1.752 ;
     RECT  20.789 2.832 21.308 5.736 ;
     RECT  20.149 14.64 21.308 21.48 ;
     RECT  21.308 1.728 21.604 21.48 ;
     RECT  21.604 2.784 22.499 2.856 ;
     RECT  22.499 2.832 23.42 2.856 ;
     RECT  21.604 3.888 23.42 5.208 ;
     RECT  21.604 1.728 24.008 1.752 ;
     RECT  23.42 2.832 24.008 5.208 ;
     RECT  21.604 13.824 24.008 21.48 ;
     RECT  24.008 1.728 24.304 21.48 ;
     RECT  24.304 3.648 25.513 4.728 ;
     RECT  25.513 3.552 25.981 4.728 ;
     RECT  24.304 1.728 26.708 1.752 ;
     RECT  25.981 3.408 26.708 4.728 ;
     RECT  24.304 13.824 26.708 21.48 ;
     RECT  26.708 1.728 27.004 21.48 ;
     RECT  27.004 3.408 27.317 4.968 ;
     RECT  27.004 13.104 27.809 21.48 ;
     RECT  27.809 13.104 27.893 21.528 ;
     RECT  27.893 13.104 28.067 21.48 ;
     RECT  27.317 4.704 28.105 4.968 ;
     RECT  27.004 1.728 29.408 1.752 ;
     RECT  28.861 3.6 29.408 3.624 ;
     RECT  28.105 4.704 29.408 5.16 ;
     RECT  28.067 13.824 29.408 21.48 ;
     RECT  29.408 1.728 29.704 21.48 ;
     RECT  29.704 3.6 30.305 4.968 ;
     RECT  30.305 3.936 31.669 4.968 ;
     RECT  29.704 1.728 32.108 1.752 ;
     RECT  31.669 3.408 32.108 4.968 ;
     RECT  29.704 13.824 32.108 21.48 ;
     RECT  32.108 1.728 32.404 21.48 ;
     RECT  32.404 13.824 33.041 21.48 ;
     RECT  32.404 1.728 33.113 5.112 ;
     RECT  33.113 3.936 33.437 5.112 ;
     RECT  33.041 13.824 33.653 21.432 ;
     RECT  33.653 14.928 34.403 21.432 ;
     RECT  33.437 4.224 34.549 5.112 ;
     RECT  34.549 3.984 34.729 5.112 ;
     RECT  33.113 1.728 34.765 2.472 ;
     RECT  34.729 3.936 34.801 5.112 ;
     RECT  34.765 1.728 34.808 2.568 ;
     RECT  34.801 3.888 34.808 5.112 ;
     RECT  33.653 13.824 34.808 13.896 ;
     RECT  34.403 14.928 34.808 21.384 ;
     RECT  34.808 1.728 35.104 21.384 ;
     RECT  35.104 14.928 35.171 21.384 ;
     RECT  35.104 1.728 35.219 2.808 ;
     RECT  35.104 3.888 36.173 5.112 ;
     RECT  36.173 3.888 36.245 4.968 ;
     RECT  35.171 14.928 36.245 21.336 ;
     RECT  35.219 2.784 37.285 2.808 ;
     RECT  36.245 3.984 37.285 4.968 ;
     RECT  35.219 1.728 37.508 1.752 ;
     RECT  37.285 2.784 37.508 4.968 ;
     RECT  35.104 13.824 37.508 13.896 ;
     RECT  36.245 14.928 37.508 15.288 ;
     RECT  36.245 16.272 37.508 21.336 ;
     RECT  37.508 1.728 37.804 21.336 ;
     RECT  37.804 16.848 38.627 21.336 ;
     RECT  37.804 2.832 38.771 4.968 ;
     RECT  37.804 14.928 39.161 15.288 ;
     RECT  37.804 13.824 39.661 13.896 ;
     RECT  39.161 14.928 39.661 14.952 ;
     RECT  38.771 2.832 40.093 2.856 ;
     RECT  38.771 3.984 40.093 4.968 ;
     RECT  37.804 1.728 40.208 1.752 ;
     RECT  40.093 2.832 40.208 4.968 ;
     RECT  39.661 13.824 40.208 14.952 ;
     RECT  38.627 16.848 40.208 20.664 ;
     RECT  40.208 1.728 40.504 20.664 ;
     RECT  40.504 16.848 41.363 20.664 ;
     RECT  40.504 3.408 41.861 4.968 ;
     RECT  41.363 16.848 42.829 20.568 ;
     RECT  40.504 1.728 42.908 1.752 ;
     RECT  41.861 3.408 42.908 3.432 ;
     RECT  41.861 4.752 42.908 4.968 ;
     RECT  40.504 13.824 42.908 13.896 ;
     RECT  40.504 14.928 42.908 14.952 ;
     RECT  42.829 16.848 42.908 20.616 ;
     RECT  42.908 1.728 43.204 20.616 ;
     RECT  43.204 13.872 43.553 13.896 ;
     RECT  43.204 16.848 43.571 20.616 ;
     RECT  43.204 4.56 44.233 4.968 ;
     RECT  43.204 3.408 44.245 3.432 ;
     RECT  44.233 4.56 44.317 5.16 ;
     RECT  43.571 16.848 45.065 20.568 ;
     RECT  43.204 14.928 45.601 14.952 ;
     RECT  43.204 1.728 45.608 1.752 ;
     RECT  44.245 2.784 45.608 3.432 ;
     RECT  44.317 4.56 45.608 5.064 ;
     RECT  45.601 14.928 45.608 15.48 ;
     RECT  45.065 16.848 45.608 19.56 ;
     RECT  45.608 1.728 45.904 19.56 ;
     RECT  45.904 19.44 46.045 19.56 ;
     RECT  45.904 14.928 46.163 15.48 ;
     RECT  45.065 20.544 46.249 20.568 ;
     RECT  46.249 19.824 46.645 20.568 ;
     RECT  46.163 14.928 46.721 14.952 ;
     RECT  45.904 2.784 46.897 2.856 ;
     RECT  45.904 4.704 47.333 5.064 ;
     RECT  46.645 19.824 47.555 20.616 ;
     RECT  46.897 2.784 48.301 3.432 ;
     RECT  45.904 1.728 48.308 1.752 ;
     RECT  48.301 2.784 48.308 3.624 ;
     RECT  47.333 5.04 48.308 5.064 ;
     RECT  45.904 16.848 48.308 18.456 ;
     RECT  47.555 19.824 48.308 20.088 ;
     RECT  48.308 1.728 48.604 20.088 ;
     RECT  48.604 16.56 48.803 20.088 ;
     RECT  48.803 18.432 48.985 20.088 ;
     RECT  48.985 18.432 49.091 20.568 ;
     RECT  48.803 16.56 49.235 17.448 ;
     RECT  48.604 3.36 49.573 4.008 ;
     RECT  48.604 5.04 49.573 5.064 ;
     RECT  49.573 3.36 49.673 5.064 ;
     RECT  49.091 18.432 49.763 19.992 ;
     RECT  49.235 16.848 49.961 17.448 ;
     RECT  49.961 17.424 50.029 17.448 ;
     RECT  49.763 18.432 50.029 18.936 ;
     RECT  49.763 19.968 50.245 19.992 ;
     RECT  49.673 4.512 50.396 5.064 ;
     RECT  50.245 19.968 50.537 20.568 ;
     RECT  49.673 3.36 50.713 3.384 ;
     RECT  50.537 19.968 50.963 20.088 ;
     RECT  50.029 17.424 50.965 18.936 ;
     RECT  50.963 19.968 50.965 19.992 ;
     RECT  50.965 17.424 50.969 19.992 ;
     RECT  48.604 1.728 51.008 1.752 ;
     RECT  50.713 3.36 51.008 3.432 ;
     RECT  50.396 4.512 51.008 5.16 ;
     RECT  50.969 17.424 51.008 19.608 ;
     RECT  51.008 1.728 51.155 19.608 ;
     RECT  51.155 1.728 51.299 19.56 ;
     RECT  51.299 1.728 51.304 19.368 ;
     RECT  51.304 3.408 51.473 3.432 ;
     RECT  51.304 1.728 51.725 1.752 ;
     RECT  51.304 4.512 51.797 4.536 ;
     RECT  51.304 17.424 51.869 19.368 ;
     RECT  51.869 17.424 52.337 18.456 ;
     RECT  52.337 17.424 52.589 18.216 ;
     RECT  52.589 17.424 53.708 17.448 ;
     RECT  53.708 2.148 53.812 19.452 ;
     RECT  53.812 2.418 54.004 19.182 ;
    LAYER M5 ;
     RECT  4.512 0.144 51.672 1.763 ;
     RECT  2.4 2.137 2.52 2.151 ;
     RECT  53.7 2.137 53.82 2.151 ;
     RECT  21.3 1.763 21.612 2.773 ;
     RECT  15.9 1.763 16.212 2.821 ;
     RECT  18.6 1.763 18.912 2.821 ;
     RECT  21.3 2.773 22.488 2.821 ;
     RECT  37.5 1.763 37.812 2.821 ;
     RECT  10.5 1.763 10.92 3.349 ;
     RECT  5.1 1.763 5.412 3.397 ;
     RECT  10.272 3.349 10.92 3.397 ;
     RECT  12.192 2.821 12.216 3.397 ;
     RECT  10.272 3.397 12.216 3.443 ;
     RECT  18.6 2.821 19.848 3.443 ;
     RECT  15.9 2.821 17.112 3.539 ;
     RECT  37.5 2.821 38.76 3.587 ;
     RECT  24 1.763 24.312 3.733 ;
     RECT  32.1 1.763 32.412 3.925 ;
     RECT  49.584 3.349 49.608 4.115 ;
     RECT  51 1.763 51.312 4.501 ;
     RECT  10.272 3.443 11.304 4.595 ;
     RECT  20.832 2.821 22.488 4.595 ;
     RECT  34.8 1.763 35.208 4.595 ;
     RECT  30.768 3.925 30.792 4.643 ;
     RECT  37.5 3.587 38.376 4.643 ;
     RECT  5.1 3.397 6.12 4.691 ;
     RECT  32.1 3.925 33.384 4.691 ;
     RECT  14.784 3.397 14.808 4.883 ;
     RECT  26.7 1.763 27.012 4.933 ;
     RECT  28.08 1.763 28.104 4.933 ;
     RECT  23.472 3.733 24.312 4.979 ;
     RECT  26.7 4.933 28.104 4.979 ;
     RECT  5.1 4.691 5.412 5.125 ;
     RECT  23.904 4.979 24.312 5.171 ;
     RECT  44.256 2.773 44.28 5.171 ;
     RECT  50.448 4.501 51.312 5.171 ;
     RECT  20.832 4.595 21.612 5.747 ;
     RECT  4.176 5.125 5.412 6.035 ;
     RECT  26.7 4.979 27.96 13.093 ;
     RECT  26.7 13.093 28.056 13.139 ;
     RECT  21.3 5.747 21.612 13.813 ;
     RECT  24 5.171 24.312 13.861 ;
     RECT  23.904 13.861 24.312 14.917 ;
     RECT  20.16 14.629 20.184 14.965 ;
     RECT  21.3 13.813 22.584 14.965 ;
     RECT  15.9 3.539 16.212 15.013 ;
     RECT  18.6 3.443 18.912 15.205 ;
     RECT  45.6 1.763 45.912 15.445 ;
     RECT  10.5 4.595 10.812 15.925 ;
     RECT  15.9 15.013 17.064 16.021 ;
     RECT  20.16 14.965 22.584 16.261 ;
     RECT  32.1 4.691 32.412 16.261 ;
     RECT  15.9 16.021 17.256 16.357 ;
     RECT  20.16 16.261 22.824 16.451 ;
     RECT  15.792 16.357 17.256 16.501 ;
     RECT  34.8 4.595 35.112 16.549 ;
     RECT  48.3 1.763 48.612 16.549 ;
     RECT  29.4 1.763 29.712 16.645 ;
     RECT  30.768 16.261 30.792 16.645 ;
     RECT  18.48 15.205 18.912 16.789 ;
     RECT  20.16 16.451 22.584 16.789 ;
     RECT  29.4 16.645 30.792 16.837 ;
     RECT  29.4 16.837 30.84 16.885 ;
     RECT  29.4 16.885 31.032 16.933 ;
     RECT  32.1 16.261 32.76 16.933 ;
     RECT  48.3 16.549 49.224 17.077 ;
     RECT  26.7 13.139 27.012 17.653 ;
     RECT  28.032 13.139 28.056 17.653 ;
     RECT  45.6 15.445 46.152 17.653 ;
     RECT  51 5.171 51.312 17.653 ;
     RECT  10.5 15.925 10.92 17.701 ;
     RECT  18.48 16.789 22.584 17.701 ;
     RECT  15.792 16.501 17.4 17.893 ;
     RECT  26.7 17.653 28.056 17.893 ;
     RECT  15.168 17.893 17.4 18.133 ;
     RECT  13.2 1.763 13.512 18.181 ;
     RECT  50.448 17.653 51.312 18.181 ;
     RECT  11.904 15.349 11.928 18.229 ;
     RECT  13.2 18.181 13.992 18.229 ;
     RECT  26.304 17.893 28.056 18.229 ;
     RECT  29.4 16.933 32.76 18.229 ;
     RECT  40.2 1.763 40.512 18.229 ;
     RECT  45.6 17.653 46.488 18.229 ;
     RECT  47.664 17.077 49.224 18.229 ;
     RECT  42.9 1.763 43.212 18.277 ;
     RECT  14.976 18.133 17.4 18.517 ;
     RECT  18.432 17.701 22.584 18.517 ;
     RECT  5.1 6.035 5.412 18.757 ;
     RECT  26.304 18.229 32.76 18.757 ;
     RECT  5.1 18.757 6.6 18.805 ;
     RECT  7.8 1.763 8.112 18.805 ;
     RECT  9.168 18.229 9.192 18.805 ;
     RECT  10.32 17.701 10.92 18.805 ;
     RECT  11.904 18.229 13.992 18.805 ;
     RECT  42.192 18.277 43.212 18.805 ;
     RECT  45.12 18.229 49.224 18.805 ;
     RECT  50.448 18.181 51.48 18.805 ;
     RECT  4.512 18.805 13.992 19.333 ;
     RECT  14.976 18.517 22.584 19.333 ;
     RECT  42.192 18.805 51.48 19.333 ;
     RECT  37.5 4.643 37.812 19.381 ;
     RECT  39.072 18.229 40.824 19.381 ;
     RECT  42 19.333 51.672 19.381 ;
     RECT  2.4 2.151 2.712 19.449 ;
     RECT  37.008 19.381 37.812 19.449 ;
     RECT  53.7 2.151 54.012 19.449 ;
     RECT  2.4 19.449 2.52 19.463 ;
     RECT  26.16 18.757 32.76 19.463 ;
     RECT  37.008 19.449 37.62 19.463 ;
     RECT  53.7 19.449 53.82 19.463 ;
     RECT  4.512 19.333 22.584 19.669 ;
     RECT  23.904 14.917 24.792 19.669 ;
     RECT  26.16 19.463 31.224 19.909 ;
     RECT  34.272 16.549 35.112 19.957 ;
     RECT  39.072 19.381 51.672 19.957 ;
     RECT  37.008 19.463 37.032 20.101 ;
     RECT  4.512 19.669 24.792 20.533 ;
     RECT  25.968 19.909 31.224 20.533 ;
     RECT  32.544 19.463 32.76 20.533 ;
     RECT  34.272 19.957 35.352 20.533 ;
     RECT  36.672 20.101 37.032 20.533 ;
     RECT  38.928 19.957 51.672 20.533 ;
     RECT  4.512 20.533 51.672 21.456 ;
     RECT  18.672 21.456 18.696 21.491 ;
     RECT  27.84 21.456 27.864 21.539 ;
  END
END hbfd_rly_136_SN_fc_f2
END LIBRARY
